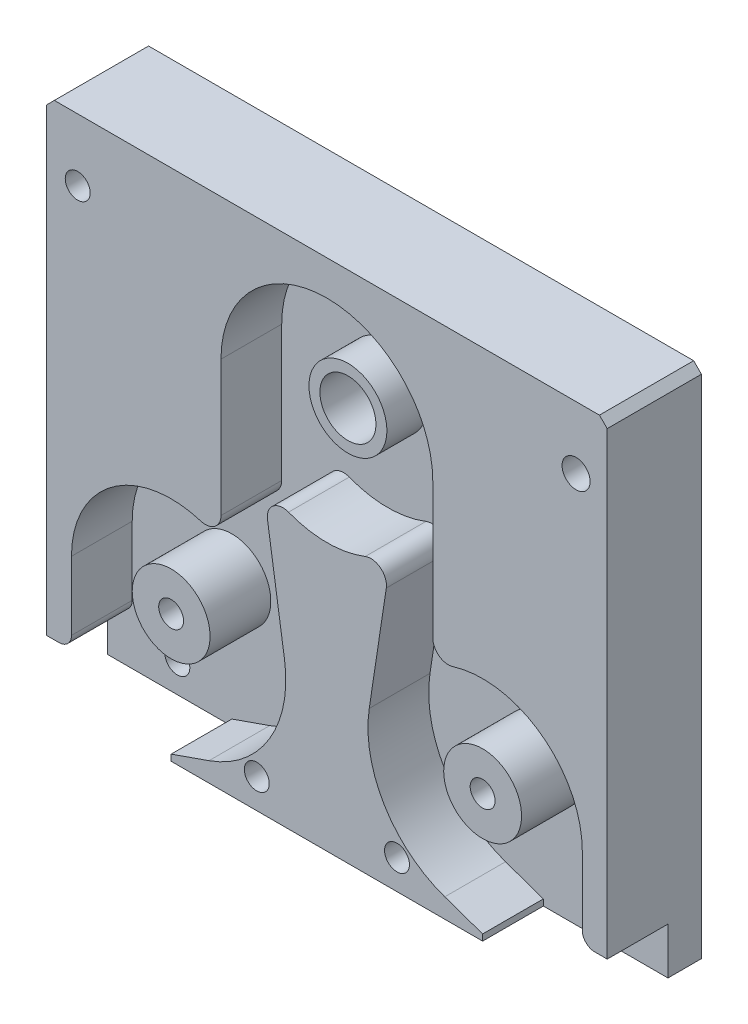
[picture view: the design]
ISO-10303-21;
HEADER;
FILE_DESCRIPTION(('STEP AP214'),'2;1');
FILE_NAME('part.step','',(''),(''),'','','');
FILE_SCHEMA(('AUTOMOTIVE_DESIGN { 1 0 10303 214 1 1 1 1 }'));
ENDSEC;
DATA;
#1=APPLICATION_CONTEXT('core data for automotive mechanical design processes');
#2=APPLICATION_PROTOCOL_DEFINITION('international standard','automotive_design',2000,#1);
#3=PRODUCT_CONTEXT('',#1,'mechanical');
#4=PRODUCT('Part','Part','',(#3));
#5=PRODUCT_RELATED_PRODUCT_CATEGORY('part','',(#4));
#6=PRODUCT_DEFINITION_FORMATION('','',#4);
#7=PRODUCT_DEFINITION_CONTEXT('part definition',#1,'design');
#8=PRODUCT_DEFINITION('design','',#6,#7);
#9=PRODUCT_DEFINITION_SHAPE('','',#8);
#10=(LENGTH_UNIT() NAMED_UNIT(*) SI_UNIT(.MILLI.,.METRE.));
#11=(NAMED_UNIT(*) PLANE_ANGLE_UNIT() SI_UNIT($,.RADIAN.));
#12=(NAMED_UNIT(*) SI_UNIT($,.STERADIAN.) SOLID_ANGLE_UNIT());
#13=UNCERTAINTY_MEASURE_WITH_UNIT(LENGTH_MEASURE(1.E-05),#10,'distance_accuracy_value','');
#14=(GEOMETRIC_REPRESENTATION_CONTEXT(3) GLOBAL_UNCERTAINTY_ASSIGNED_CONTEXT((#13)) GLOBAL_UNIT_ASSIGNED_CONTEXT((#10,
#11,#12)) REPRESENTATION_CONTEXT('',''));
#15=CARTESIAN_POINT('',(0.,0.,0.));
#16=DIRECTION('',(0.,0.,1.));
#17=DIRECTION('',(1.,0.,0.));
#18=AXIS2_PLACEMENT_3D('',#15,#16,#17);
#19=CARTESIAN_POINT('',(-50.,42.5,-20.));
#20=DIRECTION('',(0.,0.,-1.));
#21=DIRECTION('',(-1.,0.,0.));
#22=AXIS2_PLACEMENT_3D('',#19,#20,#21);
#23=PLANE('',#22);
#24=CARTESIAN_POINT('',(-50.,42.5,-20.));
#25=DIRECTION('',(0.,0.,-1.));
#26=DIRECTION('',(-1.,0.,0.));
#27=AXIS2_PLACEMENT_3D('',#24,#25,#26);
#28=CIRCLE('',#27,4.);
#29=CARTESIAN_POINT('',(-54.,42.5,-20.));
#30=VERTEX_POINT('',#29);
#31=EDGE_CURVE('E20',#30,#30,#28,.F.);
#32=ORIENTED_EDGE('',*,*,#31,.T.);
#33=EDGE_LOOP('',(#32));
#34=FACE_BOUND('',#33,.T.);
#35=ADVANCED_FACE('F16',(#34),#23,.F.);
#36=CARTESIAN_POINT('',(-50.,42.5,0.));
#37=DIRECTION('',(0.,0.,-1.));
#38=DIRECTION('',(-1.,0.,0.));
#39=AXIS2_PLACEMENT_3D('',#36,#37,#38);
#40=CYLINDRICAL_SURFACE('',#39,4.);
#41=CARTESIAN_POINT('',(-50.,42.5,0.));
#42=DIRECTION('',(0.,0.,-1.));
#43=DIRECTION('',(-1.,0.,0.));
#44=AXIS2_PLACEMENT_3D('',#41,#42,#43);
#45=CIRCLE('',#44,4.);
#46=CARTESIAN_POINT('',(-54.,42.5,0.));
#47=VERTEX_POINT('',#46);
#48=EDGE_CURVE('E498',#47,#47,#45,.T.);
#49=ORIENTED_EDGE('',*,*,#48,.F.);
#50=EDGE_LOOP('',(#49));
#51=FACE_BOUND('',#50,.T.);
#52=ORIENTED_EDGE('',*,*,#31,.F.);
#53=EDGE_LOOP('',(#52));
#54=FACE_BOUND('',#53,.T.);
#55=ADVANCED_FACE('F506',(#51,#54),#40,.F.);
#56=CARTESIAN_POINT('',(-80.,146.5,-20.));
#57=DIRECTION('',(0.,0.,-1.));
#58=DIRECTION('',(-1.,0.,0.));
#59=AXIS2_PLACEMENT_3D('',#56,#57,#58);
#60=PLANE('',#59);
#61=CARTESIAN_POINT('',(-80.,146.5,-20.));
#62=DIRECTION('',(0.,0.,-1.));
#63=DIRECTION('',(-1.,0.,0.));
#64=AXIS2_PLACEMENT_3D('',#61,#62,#63);
#65=CIRCLE('',#64,4.);
#66=CARTESIAN_POINT('',(-84.,146.5,-20.));
#67=VERTEX_POINT('',#66);
#68=EDGE_CURVE('E496',#67,#67,#65,.F.);
#69=ORIENTED_EDGE('',*,*,#68,.T.);
#70=EDGE_LOOP('',(#69));
#71=FACE_BOUND('',#70,.T.);
#72=ADVANCED_FACE('F508',(#71),#60,.F.);
#73=CARTESIAN_POINT('',(0.,84.,0.));
#74=DIRECTION('',(0.,0.,1.));
#75=DIRECTION('',(1.,0.,0.));
#76=AXIS2_PLACEMENT_3D('',#73,#74,#75);
#77=PLANE('',#76);
#78=CARTESIAN_POINT('',(50.,42.5,0.));
#79=DIRECTION('',(0.,0.,-1.));
#80=DIRECTION('',(-1.,0.,0.));
#81=AXIS2_PLACEMENT_3D('',#78,#79,#80);
#82=CIRCLE('',#81,4.);
#83=CARTESIAN_POINT('',(45.9999999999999,42.5,0.));
#84=VERTEX_POINT('',#83);
#85=EDGE_CURVE('E335',#84,#84,#82,.T.);
#86=ORIENTED_EDGE('',*,*,#85,.T.);
#87=EDGE_LOOP('',(#86));
#88=FACE_BOUND('',#87,.T.);
#89=CARTESIAN_POINT('',(50.,42.5,0.));
#90=DIRECTION('',(0.,0.,-1.));
#91=DIRECTION('',(-1.,0.,0.));
#92=AXIS2_PLACEMENT_3D('',#89,#90,#91);
#93=CIRCLE('',#92,12.5);
#94=CARTESIAN_POINT('',(37.5,42.5,0.));
#95=VERTEX_POINT('',#94);
#96=EDGE_CURVE('E239',#95,#95,#93,.T.);
#97=ORIENTED_EDGE('',*,*,#96,.F.);
#98=EDGE_LOOP('',(#97));
#99=FACE_BOUND('',#98,.T.);
#100=ADVANCED_FACE('F516',(#88,#99),#77,.T.);
#101=CARTESIAN_POINT('',(0.,84.,0.));
#102=DIRECTION('',(0.,0.,1.));
#103=DIRECTION('',(1.,0.,0.));
#104=AXIS2_PLACEMENT_3D('',#101,#102,#103);
#105=PLANE('',#104);
#106=ORIENTED_EDGE('',*,*,#48,.T.);
#107=EDGE_LOOP('',(#106));
#108=FACE_BOUND('',#107,.T.);
#109=CARTESIAN_POINT('',(-50.,42.5,0.));
#110=DIRECTION('',(0.,0.,-1.));
#111=DIRECTION('',(-1.,0.,0.));
#112=AXIS2_PLACEMENT_3D('',#109,#110,#111);
#113=CIRCLE('',#112,12.5);
#114=CARTESIAN_POINT('',(-62.5,42.5,0.));
#115=VERTEX_POINT('',#114);
#116=EDGE_CURVE('E268',#115,#115,#113,.T.);
#117=ORIENTED_EDGE('',*,*,#116,.F.);
#118=EDGE_LOOP('',(#117));
#119=FACE_BOUND('',#118,.T.);
#120=ADVANCED_FACE('F704',(#108,#119),#105,.T.);
#121=CARTESIAN_POINT('',(-80.,146.5,0.));
#122=DIRECTION('',(0.,0.,-1.));
#123=DIRECTION('',(-1.,0.,0.));
#124=AXIS2_PLACEMENT_3D('',#121,#122,#123);
#125=CYLINDRICAL_SURFACE('',#124,4.);
#126=CARTESIAN_POINT('',(-80.,146.5,0.));
#127=DIRECTION('',(0.,0.,-1.));
#128=DIRECTION('',(-1.,0.,0.));
#129=AXIS2_PLACEMENT_3D('',#126,#127,#128);
#130=CIRCLE('',#129,4.);
#131=CARTESIAN_POINT('',(-84.,146.5,0.));
#132=VERTEX_POINT('',#131);
#133=EDGE_CURVE('E471',#132,#132,#130,.T.);
#134=ORIENTED_EDGE('',*,*,#133,.F.);
#135=EDGE_LOOP('',(#134));
#136=FACE_BOUND('',#135,.T.);
#137=ORIENTED_EDGE('',*,*,#68,.F.);
#138=EDGE_LOOP('',(#137));
#139=FACE_BOUND('',#138,.T.);
#140=ADVANCED_FACE('F700',(#136,#139),#125,.F.);
#141=CARTESIAN_POINT('',(50.,42.5,0.));
#142=DIRECTION('',(0.,0.,-1.));
#143=DIRECTION('',(-1.,0.,0.));
#144=AXIS2_PLACEMENT_3D('',#141,#142,#143);
#145=CYLINDRICAL_SURFACE('',#144,4.);
#146=ORIENTED_EDGE('',*,*,#85,.F.);
#147=EDGE_LOOP('',(#146));
#148=FACE_BOUND('',#147,.T.);
#149=CARTESIAN_POINT('',(50.,42.5,-21.25));
#150=DIRECTION('',(0.,0.,-1.));
#151=DIRECTION('',(-1.,0.,0.));
#152=AXIS2_PLACEMENT_3D('',#149,#150,#151);
#153=CIRCLE('',#152,4.);
#154=CARTESIAN_POINT('',(45.9999999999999,42.5,-21.25));
#155=VERTEX_POINT('',#154);
#156=EDGE_CURVE('E462',#155,#155,#153,.T.);
#157=ORIENTED_EDGE('',*,*,#156,.T.);
#158=EDGE_LOOP('',(#157));
#159=FACE_BOUND('',#158,.T.);
#160=ADVANCED_FACE('F696',(#148,#159),#145,.F.);
#161=CARTESIAN_POINT('',(79.9999999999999,146.5,0.));
#162=DIRECTION('',(0.,0.,-1.));
#163=DIRECTION('',(-1.,0.,0.));
#164=AXIS2_PLACEMENT_3D('',#161,#162,#163);
#165=CYLINDRICAL_SURFACE('',#164,4.5);
#166=CARTESIAN_POINT('',(79.9999999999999,146.5,0.));
#167=DIRECTION('',(0.,0.,-1.));
#168=DIRECTION('',(-1.,0.,0.));
#169=AXIS2_PLACEMENT_3D('',#166,#167,#168);
#170=CIRCLE('',#169,4.5);
#171=CARTESIAN_POINT('',(75.4999999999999,146.5,0.));
#172=VERTEX_POINT('',#171);
#173=EDGE_CURVE('E468',#172,#172,#170,.T.);
#174=ORIENTED_EDGE('',*,*,#173,.F.);
#175=EDGE_LOOP('',(#174));
#176=FACE_BOUND('',#175,.T.);
#177=CARTESIAN_POINT('',(79.9999999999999,146.5,-21.25));
#178=DIRECTION('',(0.,0.,-1.));
#179=DIRECTION('',(-1.,0.,0.));
#180=AXIS2_PLACEMENT_3D('',#177,#178,#179);
#181=CIRCLE('',#180,4.5);
#182=CARTESIAN_POINT('',(75.4999999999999,146.5,-21.25));
#183=VERTEX_POINT('',#182);
#184=EDGE_CURVE('E354',#183,#183,#181,.T.);
#185=ORIENTED_EDGE('',*,*,#184,.T.);
#186=EDGE_LOOP('',(#185));
#187=FACE_BOUND('',#186,.T.);
#188=ADVANCED_FACE('F692',(#176,#187),#165,.F.);
#189=CARTESIAN_POINT('',(-50.,3.5,0.));
#190=DIRECTION('',(0.330013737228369,-0.943976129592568,0.));
#191=DIRECTION('',(0.943976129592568,0.330013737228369,0.));
#192=AXIS2_PLACEMENT_3D('',#189,#190,#191);
#193=PLANE('',#192);
#194=DIRECTION('',(0.,0.,-1.));
#195=VECTOR('',#194,1.);
#196=CARTESIAN_POINT('',(-50.,3.5,0.));
#197=LINE('',#196,#195);
#198=CARTESIAN_POINT('',(-50.,3.5,-19.5));
#199=VERTEX_POINT('',#198);
#200=CARTESIAN_POINT('',(-50.,3.5,0.));
#201=VERTEX_POINT('',#200);
#202=EDGE_CURVE('E301',#199,#201,#197,.F.);
#203=ORIENTED_EDGE('',*,*,#202,.T.);
#204=DIRECTION('',(-0.943976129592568,-0.330013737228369,0.));
#205=VECTOR('',#204,1.);
#206=CARTESIAN_POINT('',(-37.8505214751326,7.74745360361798,0.));
#207=LINE('',#206,#205);
#208=CARTESIAN_POINT('',(-37.8505214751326,7.74745360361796,0.));
#209=VERTEX_POINT('',#208);
#210=EDGE_CURVE('E349',#209,#201,#207,.T.);
#211=ORIENTED_EDGE('',*,*,#210,.F.);
#212=DIRECTION('',(0.,0.,-1.));
#213=VECTOR('',#212,1.);
#214=CARTESIAN_POINT('',(-37.8505214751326,7.74745360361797,0.));
#215=LINE('',#214,#213);
#216=CARTESIAN_POINT('',(-37.8505214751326,7.74745360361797,-19.5));
#217=VERTEX_POINT('',#216);
#218=EDGE_CURVE('E332',#209,#217,#215,.T.);
#219=ORIENTED_EDGE('',*,*,#218,.T.);
#220=DIRECTION('',(0.943976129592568,0.33001373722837,0.));
#221=VECTOR('',#220,1.);
#222=CARTESIAN_POINT('',(-50.,3.5,-19.5));
#223=LINE('',#222,#221);
#224=EDGE_CURVE('E339',#199,#217,#223,.T.);
#225=ORIENTED_EDGE('',*,*,#224,.F.);
#226=EDGE_LOOP('',(#203,#211,#219,#225));
#227=FACE_BOUND('',#226,.T.);
#228=ADVANCED_FACE('F688',(#227),#193,.F.);
#229=CARTESIAN_POINT('',(-50.,42.5,0.));
#230=DIRECTION('',(0.,0.,-1.));
#231=DIRECTION('',(-1.,0.,0.));
#232=AXIS2_PLACEMENT_3D('',#229,#230,#231);
#233=CYLINDRICAL_SURFACE('',#232,36.8150690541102);
#234=ORIENTED_EDGE('',*,*,#218,.F.);
#235=CARTESIAN_POINT('',(-50.,42.5,0.));
#236=DIRECTION('',(0.,0.,-1.));
#237=DIRECTION('',(-1.,0.,0.));
#238=AXIS2_PLACEMENT_3D('',#235,#236,#237);
#239=CIRCLE('',#238,36.8150690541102);
#240=CARTESIAN_POINT('',(-13.5982629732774,48.0011681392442,0.));
#241=VERTEX_POINT('',#240);
#242=EDGE_CURVE('E443',#241,#209,#239,.T.);
#243=ORIENTED_EDGE('',*,*,#242,.F.);
#244=DIRECTION('',(0.,0.,1.));
#245=VECTOR('',#244,1.);
#246=CARTESIAN_POINT('',(-13.5982629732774,48.0011681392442,0.));
#247=LINE('',#246,#245);
#248=CARTESIAN_POINT('',(-13.5982629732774,48.0011681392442,-19.5));
#249=VERTEX_POINT('',#248);
#250=EDGE_CURVE('E329',#241,#249,#247,.F.);
#251=ORIENTED_EDGE('',*,*,#250,.T.);
#252=CARTESIAN_POINT('',(-50.,42.5,-19.5));
#253=DIRECTION('',(0.,0.,-1.));
#254=DIRECTION('',(-1.,0.,0.));
#255=AXIS2_PLACEMENT_3D('',#252,#253,#254);
#256=CIRCLE('',#255,36.8150690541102);
#257=EDGE_CURVE('E441',#217,#249,#256,.F.);
#258=ORIENTED_EDGE('',*,*,#257,.F.);
#259=EDGE_LOOP('',(#234,#243,#251,#258));
#260=FACE_BOUND('',#259,.T.);
#261=ADVANCED_FACE('F684',(#260),#233,.F.);
#262=CARTESIAN_POINT('',(-13.5982629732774,48.0011681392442,0.));
#263=DIRECTION('',(0.988772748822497,0.149427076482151,0.));
#264=DIRECTION('',(-0.149427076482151,0.988772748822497,0.));
#265=AXIS2_PLACEMENT_3D('',#262,#263,#264);
#266=PLANE('',#265);
#267=ORIENTED_EDGE('',*,*,#250,.F.);
#268=DIRECTION('',(0.149427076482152,-0.988772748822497,0.));
#269=VECTOR('',#268,1.);
#270=CARTESIAN_POINT('',(-19.0688637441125,84.2006380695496,0.));
#271=LINE('',#270,#269);
#272=CARTESIAN_POINT('',(-19.0688637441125,84.2006380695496,0.));
#273=VERTEX_POINT('',#272);
#274=EDGE_CURVE('E446',#273,#241,#271,.T.);
#275=ORIENTED_EDGE('',*,*,#274,.F.);
#276=DIRECTION('',(0.,0.,-1.));
#277=VECTOR('',#276,1.);
#278=CARTESIAN_POINT('',(-19.0688637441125,84.2006380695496,0.));
#279=LINE('',#278,#277);
#280=CARTESIAN_POINT('',(-19.0688637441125,84.2006380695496,-19.5));
#281=VERTEX_POINT('',#280);
#282=EDGE_CURVE('E327',#281,#273,#279,.F.);
#283=ORIENTED_EDGE('',*,*,#282,.F.);
#284=DIRECTION('',(-0.149427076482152,0.988772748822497,0.));
#285=VECTOR('',#284,1.);
#286=CARTESIAN_POINT('',(-13.5982629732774,48.0011681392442,-19.5));
#287=LINE('',#286,#285);
#288=EDGE_CURVE('E440',#249,#281,#287,.T.);
#289=ORIENTED_EDGE('',*,*,#288,.F.);
#290=EDGE_LOOP('',(#267,#275,#283,#289));
#291=FACE_BOUND('',#290,.T.);
#292=ADVANCED_FACE('F680',(#291),#266,.F.);
#293=CARTESIAN_POINT('',(-14.125,84.9477734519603,0.));
#294=DIRECTION('',(0.,0.,-1.));
#295=DIRECTION('',(-1.,0.,0.));
#296=AXIS2_PLACEMENT_3D('',#293,#294,#295);
#297=CYLINDRICAL_SURFACE('',#296,5.);
#298=CARTESIAN_POINT('',(-14.125,84.9477734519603,0.));
#299=DIRECTION('',(0.,0.,-1.));
#300=DIRECTION('',(-1.,0.,0.));
#301=AXIS2_PLACEMENT_3D('',#298,#299,#300);
#302=CIRCLE('',#301,5.);
#303=CARTESIAN_POINT('',(-12.3141025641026,89.6083153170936,0.));
#304=VERTEX_POINT('',#303);
#305=EDGE_CURVE('E447',#304,#273,#302,.F.);
#306=ORIENTED_EDGE('',*,*,#305,.F.);
#307=DIRECTION('',(0.,0.,-1.));
#308=VECTOR('',#307,1.);
#309=CARTESIAN_POINT('',(-12.3141025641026,89.6083153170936,0.));
#310=LINE('',#309,#308);
#311=CARTESIAN_POINT('',(-12.3141025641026,89.6083153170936,-19.5));
#312=VERTEX_POINT('',#311);
#313=EDGE_CURVE('E324',#304,#312,#310,.T.);
#314=ORIENTED_EDGE('',*,*,#313,.T.);
#315=CARTESIAN_POINT('',(-14.125,84.9477734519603,-19.5));
#316=DIRECTION('',(0.,0.,-1.));
#317=DIRECTION('',(-1.,0.,0.));
#318=AXIS2_PLACEMENT_3D('',#315,#316,#317);
#319=CIRCLE('',#318,5.);
#320=EDGE_CURVE('E438',#281,#312,#319,.T.);
#321=ORIENTED_EDGE('',*,*,#320,.F.);
#322=ORIENTED_EDGE('',*,*,#282,.T.);
#323=EDGE_LOOP('',(#306,#314,#321,#322));
#324=FACE_BOUND('',#323,.T.);
#325=ADVANCED_FACE('F676',(#324),#297,.T.);
#326=CARTESIAN_POINT('',(0.,121.3,0.));
#327=DIRECTION('',(0.,0.,-1.));
#328=DIRECTION('',(-1.,0.,0.));
#329=AXIS2_PLACEMENT_3D('',#326,#327,#328);
#330=CYLINDRICAL_SURFACE('',#329,34.);
#331=ORIENTED_EDGE('',*,*,#313,.F.);
#332=CARTESIAN_POINT('',(0.,121.3,0.));
#333=DIRECTION('',(0.,0.,-1.));
#334=DIRECTION('',(-1.,0.,0.));
#335=AXIS2_PLACEMENT_3D('',#332,#333,#334);
#336=CIRCLE('',#335,34.);
#337=CARTESIAN_POINT('',(12.3141025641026,89.6083153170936,0.));
#338=VERTEX_POINT('',#337);
#339=EDGE_CURVE('E450',#338,#304,#336,.T.);
#340=ORIENTED_EDGE('',*,*,#339,.F.);
#341=DIRECTION('',(0.,0.,-1.));
#342=VECTOR('',#341,1.);
#343=CARTESIAN_POINT('',(12.3141025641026,89.6083153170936,0.));
#344=LINE('',#343,#342);
#345=CARTESIAN_POINT('',(12.3141025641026,89.6083153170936,-19.5));
#346=VERTEX_POINT('',#345);
#347=EDGE_CURVE('E322',#346,#338,#344,.F.);
#348=ORIENTED_EDGE('',*,*,#347,.F.);
#349=CARTESIAN_POINT('',(0.,121.3,-19.5));
#350=DIRECTION('',(0.,0.,-1.));
#351=DIRECTION('',(-1.,0.,0.));
#352=AXIS2_PLACEMENT_3D('',#349,#350,#351);
#353=CIRCLE('',#352,34.);
#354=EDGE_CURVE('E436',#312,#346,#353,.F.);
#355=ORIENTED_EDGE('',*,*,#354,.F.);
#356=EDGE_LOOP('',(#331,#340,#348,#355));
#357=FACE_BOUND('',#356,.T.);
#358=ADVANCED_FACE('F672',(#357),#330,.F.);
#359=CARTESIAN_POINT('',(14.125,84.9477734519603,0.));
#360=DIRECTION('',(0.,0.,-1.));
#361=DIRECTION('',(-1.,0.,0.));
#362=AXIS2_PLACEMENT_3D('',#359,#360,#361);
#363=CYLINDRICAL_SURFACE('',#362,5.);
#364=CARTESIAN_POINT('',(14.125,84.9477734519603,0.));
#365=DIRECTION('',(0.,0.,-1.));
#366=DIRECTION('',(-1.,0.,0.));
#367=AXIS2_PLACEMENT_3D('',#364,#365,#366);
#368=CIRCLE('',#367,5.);
#369=CARTESIAN_POINT('',(19.0688637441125,84.2006380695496,0.));
#370=VERTEX_POINT('',#369);
#371=EDGE_CURVE('E453',#370,#338,#368,.F.);
#372=ORIENTED_EDGE('',*,*,#371,.F.);
#373=DIRECTION('',(0.,0.,1.));
#374=VECTOR('',#373,1.);
#375=CARTESIAN_POINT('',(19.0688637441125,84.2006380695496,0.));
#376=LINE('',#375,#374);
#377=CARTESIAN_POINT('',(19.0688637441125,84.2006380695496,-19.5));
#378=VERTEX_POINT('',#377);
#379=EDGE_CURVE('E319',#370,#378,#376,.F.);
#380=ORIENTED_EDGE('',*,*,#379,.T.);
#381=CARTESIAN_POINT('',(14.125,84.9477734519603,-19.5));
#382=DIRECTION('',(0.,0.,-1.));
#383=DIRECTION('',(-1.,0.,0.));
#384=AXIS2_PLACEMENT_3D('',#381,#382,#383);
#385=CIRCLE('',#384,5.);
#386=EDGE_CURVE('E434',#346,#378,#385,.T.);
#387=ORIENTED_EDGE('',*,*,#386,.F.);
#388=ORIENTED_EDGE('',*,*,#347,.T.);
#389=EDGE_LOOP('',(#372,#380,#387,#388));
#390=FACE_BOUND('',#389,.T.);
#391=ADVANCED_FACE('F668',(#390),#363,.T.);
#392=CARTESIAN_POINT('',(19.0688637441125,84.2006380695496,0.));
#393=DIRECTION('',(-0.988772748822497,0.14942707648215,0.));
#394=DIRECTION('',(-0.14942707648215,-0.988772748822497,0.));
#395=AXIS2_PLACEMENT_3D('',#392,#393,#394);
#396=PLANE('',#395);
#397=ORIENTED_EDGE('',*,*,#379,.F.);
#398=DIRECTION('',(0.14942707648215,0.988772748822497,0.));
#399=VECTOR('',#398,1.);
#400=CARTESIAN_POINT('',(13.5982629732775,48.0011681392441,0.));
#401=LINE('',#400,#399);
#402=CARTESIAN_POINT('',(13.5982629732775,48.0011681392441,0.));
#403=VERTEX_POINT('',#402);
#404=EDGE_CURVE('E456',#403,#370,#401,.T.);
#405=ORIENTED_EDGE('',*,*,#404,.F.);
#406=DIRECTION('',(0.,0.,-1.));
#407=VECTOR('',#406,1.);
#408=CARTESIAN_POINT('',(13.5982629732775,48.0011681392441,0.));
#409=LINE('',#408,#407);
#410=CARTESIAN_POINT('',(13.5982629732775,48.0011681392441,-19.5));
#411=VERTEX_POINT('',#410);
#412=EDGE_CURVE('E310',#403,#411,#409,.T.);
#413=ORIENTED_EDGE('',*,*,#412,.T.);
#414=DIRECTION('',(-0.14942707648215,-0.988772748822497,0.));
#415=VECTOR('',#414,1.);
#416=CARTESIAN_POINT('',(19.0688637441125,84.2006380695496,-19.5));
#417=LINE('',#416,#415);
#418=EDGE_CURVE('E433',#378,#411,#417,.T.);
#419=ORIENTED_EDGE('',*,*,#418,.F.);
#420=EDGE_LOOP('',(#397,#405,#413,#419));
#421=FACE_BOUND('',#420,.T.);
#422=ADVANCED_FACE('F664',(#421),#396,.F.);
#423=CARTESIAN_POINT('',(50.,42.5,0.));
#424=DIRECTION('',(0.,0.,-1.));
#425=DIRECTION('',(-1.,0.,0.));
#426=AXIS2_PLACEMENT_3D('',#423,#424,#425);
#427=CYLINDRICAL_SURFACE('',#426,36.8150690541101);
#428=ORIENTED_EDGE('',*,*,#412,.F.);
#429=CARTESIAN_POINT('',(50.,42.5,0.));
#430=DIRECTION('',(0.,0.,-1.));
#431=DIRECTION('',(-1.,0.,0.));
#432=AXIS2_PLACEMENT_3D('',#429,#430,#431);
#433=CIRCLE('',#432,36.8150690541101);
#434=CARTESIAN_POINT('',(37.8505214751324,7.74745360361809,0.));
#435=VERTEX_POINT('',#434);
#436=EDGE_CURVE('E457',#435,#403,#433,.T.);
#437=ORIENTED_EDGE('',*,*,#436,.F.);
#438=DIRECTION('',(0.,0.,1.));
#439=VECTOR('',#438,1.);
#440=CARTESIAN_POINT('',(37.8505214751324,7.7474536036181,0.));
#441=LINE('',#440,#439);
#442=CARTESIAN_POINT('',(37.8505214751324,7.7474536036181,-19.5));
#443=VERTEX_POINT('',#442);
#444=EDGE_CURVE('E299',#435,#443,#441,.F.);
#445=ORIENTED_EDGE('',*,*,#444,.T.);
#446=CARTESIAN_POINT('',(50.,42.5,-19.5));
#447=DIRECTION('',(0.,0.,-1.));
#448=DIRECTION('',(-1.,0.,0.));
#449=AXIS2_PLACEMENT_3D('',#446,#447,#448);
#450=CIRCLE('',#449,36.8150690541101);
#451=EDGE_CURVE('E431',#411,#443,#450,.F.);
#452=ORIENTED_EDGE('',*,*,#451,.F.);
#453=EDGE_LOOP('',(#428,#437,#445,#452));
#454=FACE_BOUND('',#453,.T.);
#455=ADVANCED_FACE('F660',(#454),#427,.F.);
#456=CARTESIAN_POINT('',(37.8505214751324,7.7474536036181,0.));
#457=DIRECTION('',(-0.330013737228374,-0.943976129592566,0.));
#458=DIRECTION('',(0.943976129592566,-0.330013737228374,0.));
#459=AXIS2_PLACEMENT_3D('',#456,#457,#458);
#460=PLANE('',#459);
#461=ORIENTED_EDGE('',*,*,#444,.F.);
#462=DIRECTION('',(-0.943976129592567,0.330013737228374,0.));
#463=VECTOR('',#462,1.);
#464=CARTESIAN_POINT('',(50.,3.5,0.));
#465=LINE('',#464,#463);
#466=CARTESIAN_POINT('',(50.,3.50000000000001,0.));
#467=VERTEX_POINT('',#466);
#468=EDGE_CURVE('E353',#467,#435,#465,.T.);
#469=ORIENTED_EDGE('',*,*,#468,.F.);
#470=DIRECTION('',(0.,0.,1.));
#471=VECTOR('',#470,1.);
#472=CARTESIAN_POINT('',(50.,3.5,0.));
#473=LINE('',#472,#471);
#474=CARTESIAN_POINT('',(50.,3.5,-19.5));
#475=VERTEX_POINT('',#474);
#476=EDGE_CURVE('E267',#467,#475,#473,.F.);
#477=ORIENTED_EDGE('',*,*,#476,.T.);
#478=DIRECTION('',(0.943976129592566,-0.330013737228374,0.));
#479=VECTOR('',#478,1.);
#480=CARTESIAN_POINT('',(37.8505214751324,7.7474536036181,-19.5));
#481=LINE('',#480,#479);
#482=EDGE_CURVE('E316',#443,#475,#481,.T.);
#483=ORIENTED_EDGE('',*,*,#482,.F.);
#484=EDGE_LOOP('',(#461,#469,#477,#483));
#485=FACE_BOUND('',#484,.T.);
#486=ADVANCED_FACE('F656',(#485),#460,.F.);
#487=CARTESIAN_POINT('',(86.,20.5,0.));
#488=DIRECTION('',(0.,0.,-1.));
#489=DIRECTION('',(-1.,0.,0.));
#490=AXIS2_PLACEMENT_3D('',#487,#488,#489);
#491=CYLINDRICAL_SURFACE('',#490,4.00000000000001);
#492=CARTESIAN_POINT('',(86.,20.5,0.));
#493=DIRECTION('',(0.,0.,-1.));
#494=DIRECTION('',(-1.,0.,0.));
#495=AXIS2_PLACEMENT_3D('',#492,#493,#494);
#496=CIRCLE('',#495,4.00000000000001);
#497=CARTESIAN_POINT('',(82.,20.5,0.));
#498=VERTEX_POINT('',#497);
#499=CARTESIAN_POINT('',(86.,16.5,0.));
#500=VERTEX_POINT('',#499);
#501=EDGE_CURVE('E474',#498,#500,#496,.F.);
#502=ORIENTED_EDGE('',*,*,#501,.F.);
#503=DIRECTION('',(0.,0.,-1.));
#504=VECTOR('',#503,1.);
#505=CARTESIAN_POINT('',(82.,20.5,0.));
#506=LINE('',#505,#504);
#507=CARTESIAN_POINT('',(82.,20.5,-19.5));
#508=VERTEX_POINT('',#507);
#509=EDGE_CURVE('E296',#498,#508,#506,.T.);
#510=ORIENTED_EDGE('',*,*,#509,.T.);
#511=CARTESIAN_POINT('',(86.,20.5,-19.5));
#512=DIRECTION('',(0.,0.,-1.));
#513=DIRECTION('',(-1.,0.,0.));
#514=AXIS2_PLACEMENT_3D('',#511,#512,#513);
#515=CIRCLE('',#514,4.00000000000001);
#516=CARTESIAN_POINT('',(86.,16.5,-19.5));
#517=VERTEX_POINT('',#516);
#518=EDGE_CURVE('E429',#517,#508,#515,.T.);
#519=ORIENTED_EDGE('',*,*,#518,.F.);
#520=DIRECTION('',(0.,0.,1.));
#521=VECTOR('',#520,1.);
#522=CARTESIAN_POINT('',(86.,16.5,0.));
#523=LINE('',#522,#521);
#524=EDGE_CURVE('E265',#517,#500,#523,.T.);
#525=ORIENTED_EDGE('',*,*,#524,.T.);
#526=EDGE_LOOP('',(#502,#510,#519,#525));
#527=FACE_BOUND('',#526,.T.);
#528=ADVANCED_FACE('F652',(#527),#491,.T.);
#529=CARTESIAN_POINT('',(82.,20.5,0.));
#530=DIRECTION('',(1.,0.,0.));
#531=DIRECTION('',(0.,0.,-1.));
#532=AXIS2_PLACEMENT_3D('',#529,#530,#531);
#533=PLANE('',#532);
#534=ORIENTED_EDGE('',*,*,#509,.F.);
#535=DIRECTION('',(0.,1.,0.));
#536=VECTOR('',#535,1.);
#537=CARTESIAN_POINT('',(81.9999999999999,84.,0.));
#538=LINE('',#537,#536);
#539=CARTESIAN_POINT('',(81.9999999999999,42.5,0.));
#540=VERTEX_POINT('',#539);
#541=EDGE_CURVE('E477',#540,#498,#538,.F.);
#542=ORIENTED_EDGE('',*,*,#541,.F.);
#543=DIRECTION('',(0.,0.,-1.));
#544=VECTOR('',#543,1.);
#545=CARTESIAN_POINT('',(81.9999999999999,42.5,0.));
#546=LINE('',#545,#544);
#547=CARTESIAN_POINT('',(81.9999999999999,42.5,-19.5));
#548=VERTEX_POINT('',#547);
#549=EDGE_CURVE('E293',#540,#548,#546,.T.);
#550=ORIENTED_EDGE('',*,*,#549,.T.);
#551=DIRECTION('',(0.,1.,0.));
#552=VECTOR('',#551,1.);
#553=CARTESIAN_POINT('',(82.,61.3926362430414,-19.5));
#554=LINE('',#553,#552);
#555=EDGE_CURVE('E428',#508,#548,#554,.T.);
#556=ORIENTED_EDGE('',*,*,#555,.F.);
#557=EDGE_LOOP('',(#534,#542,#550,#556));
#558=FACE_BOUND('',#557,.T.);
#559=ADVANCED_FACE('F648',(#558),#533,.F.);
#560=CARTESIAN_POINT('',(50.,42.5,0.));
#561=DIRECTION('',(0.,0.,-1.));
#562=DIRECTION('',(-1.,0.,0.));
#563=AXIS2_PLACEMENT_3D('',#560,#561,#562);
#564=CYLINDRICAL_SURFACE('',#563,32.);
#565=ORIENTED_EDGE('',*,*,#549,.F.);
#566=CARTESIAN_POINT('',(50.,42.5,0.));
#567=DIRECTION('',(0.,0.,-1.));
#568=DIRECTION('',(-1.,0.,0.));
#569=AXIS2_PLACEMENT_3D('',#566,#567,#568);
#570=CIRCLE('',#569,32.);
#571=CARTESIAN_POINT('',(40.4864864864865,73.0531186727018,0.));
#572=VERTEX_POINT('',#571);
#573=EDGE_CURVE('E478',#572,#540,#570,.T.);
#574=ORIENTED_EDGE('',*,*,#573,.F.);
#575=DIRECTION('',(0.,0.,-1.));
#576=VECTOR('',#575,1.);
#577=CARTESIAN_POINT('',(40.4864864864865,73.0531186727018,0.));
#578=LINE('',#577,#576);
#579=CARTESIAN_POINT('',(40.4864864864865,73.0531186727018,-19.5));
#580=VERTEX_POINT('',#579);
#581=EDGE_CURVE('E291',#580,#572,#578,.F.);
#582=ORIENTED_EDGE('',*,*,#581,.F.);
#583=CARTESIAN_POINT('',(50.,42.5,-19.5));
#584=DIRECTION('',(0.,0.,-1.));
#585=DIRECTION('',(-1.,0.,0.));
#586=AXIS2_PLACEMENT_3D('',#583,#584,#585);
#587=CIRCLE('',#586,32.);
#588=EDGE_CURVE('E426',#548,#580,#587,.F.);
#589=ORIENTED_EDGE('',*,*,#588,.F.);
#590=EDGE_LOOP('',(#565,#574,#582,#589));
#591=FACE_BOUND('',#590,.T.);
#592=ADVANCED_FACE('F644',(#591),#564,.F.);
#593=CARTESIAN_POINT('',(39.,77.8270434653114,0.));
#594=DIRECTION('',(0.,0.,-1.));
#595=DIRECTION('',(-1.,0.,0.));
#596=AXIS2_PLACEMENT_3D('',#593,#594,#595);
#597=CYLINDRICAL_SURFACE('',#596,5.);
#598=CARTESIAN_POINT('',(39.,77.8270434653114,0.));
#599=DIRECTION('',(0.,0.,-1.));
#600=DIRECTION('',(-1.,0.,0.));
#601=AXIS2_PLACEMENT_3D('',#598,#599,#600);
#602=CIRCLE('',#601,5.);
#603=CARTESIAN_POINT('',(34.,77.8270434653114,0.));
#604=VERTEX_POINT('',#603);
#605=EDGE_CURVE('E481',#604,#572,#602,.F.);
#606=ORIENTED_EDGE('',*,*,#605,.F.);
#607=DIRECTION('',(0.,0.,-1.));
#608=VECTOR('',#607,1.);
#609=CARTESIAN_POINT('',(34.,77.8270434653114,0.));
#610=LINE('',#609,#608);
#611=CARTESIAN_POINT('',(34.,77.8270434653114,-19.5));
#612=VERTEX_POINT('',#611);
#613=EDGE_CURVE('E288',#604,#612,#610,.T.);
#614=ORIENTED_EDGE('',*,*,#613,.T.);
#615=CARTESIAN_POINT('',(39.,77.8270434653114,-19.5));
#616=DIRECTION('',(0.,0.,-1.));
#617=DIRECTION('',(-1.,0.,0.));
#618=AXIS2_PLACEMENT_3D('',#615,#616,#617);
#619=CIRCLE('',#618,5.);
#620=EDGE_CURVE('E424',#580,#612,#619,.T.);
#621=ORIENTED_EDGE('',*,*,#620,.F.);
#622=ORIENTED_EDGE('',*,*,#581,.T.);
#623=EDGE_LOOP('',(#606,#614,#621,#622));
#624=FACE_BOUND('',#623,.T.);
#625=ADVANCED_FACE('F640',(#624),#597,.T.);
#626=CARTESIAN_POINT('',(34.,77.8270434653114,0.));
#627=DIRECTION('',(1.,0.,0.));
#628=DIRECTION('',(0.,0.,-1.));
#629=AXIS2_PLACEMENT_3D('',#626,#627,#628);
#630=PLANE('',#629);
#631=ORIENTED_EDGE('',*,*,#613,.F.);
#632=DIRECTION('',(0.,1.,0.));
#633=VECTOR('',#632,1.);
#634=CARTESIAN_POINT('',(34.,84.,0.));
#635=LINE('',#634,#633);
#636=CARTESIAN_POINT('',(34.,121.3,0.));
#637=VERTEX_POINT('',#636);
#638=EDGE_CURVE('E484',#637,#604,#635,.F.);
#639=ORIENTED_EDGE('',*,*,#638,.F.);
#640=DIRECTION('',(0.,0.,-1.));
#641=VECTOR('',#640,1.);
#642=CARTESIAN_POINT('',(34.,121.3,0.));
#643=LINE('',#642,#641);
#644=CARTESIAN_POINT('',(34.,121.3,-19.5));
#645=VERTEX_POINT('',#644);
#646=EDGE_CURVE('E285',#637,#645,#643,.T.);
#647=ORIENTED_EDGE('',*,*,#646,.T.);
#648=DIRECTION('',(0.,1.,0.));
#649=VECTOR('',#648,1.);
#650=CARTESIAN_POINT('',(34.,61.3926362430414,-19.5));
#651=LINE('',#650,#649);
#652=EDGE_CURVE('E423',#612,#645,#651,.T.);
#653=ORIENTED_EDGE('',*,*,#652,.F.);
#654=EDGE_LOOP('',(#631,#639,#647,#653));
#655=FACE_BOUND('',#654,.T.);
#656=ADVANCED_FACE('F636',(#655),#630,.F.);
#657=CARTESIAN_POINT('',(0.,121.3,0.));
#658=DIRECTION('',(0.,0.,-1.));
#659=DIRECTION('',(-1.,0.,0.));
#660=AXIS2_PLACEMENT_3D('',#657,#658,#659);
#661=CYLINDRICAL_SURFACE('',#660,34.);
#662=ORIENTED_EDGE('',*,*,#646,.F.);
#663=CARTESIAN_POINT('',(0.,121.3,0.));
#664=DIRECTION('',(0.,0.,-1.));
#665=DIRECTION('',(-1.,0.,0.));
#666=AXIS2_PLACEMENT_3D('',#663,#664,#665);
#667=CIRCLE('',#666,34.);
#668=CARTESIAN_POINT('',(-34.,121.3,0.));
#669=VERTEX_POINT('',#668);
#670=EDGE_CURVE('E485',#669,#637,#667,.T.);
#671=ORIENTED_EDGE('',*,*,#670,.F.);
#672=DIRECTION('',(0.,0.,1.));
#673=VECTOR('',#672,1.);
#674=CARTESIAN_POINT('',(-34.,121.3,0.));
#675=LINE('',#674,#673);
#676=CARTESIAN_POINT('',(-34.,121.3,-19.5));
#677=VERTEX_POINT('',#676);
#678=EDGE_CURVE('E282',#669,#677,#675,.F.);
#679=ORIENTED_EDGE('',*,*,#678,.T.);
#680=CARTESIAN_POINT('',(0.,121.3,-19.5));
#681=DIRECTION('',(0.,0.,-1.));
#682=DIRECTION('',(-1.,0.,0.));
#683=AXIS2_PLACEMENT_3D('',#680,#681,#682);
#684=CIRCLE('',#683,34.);
#685=EDGE_CURVE('E421',#645,#677,#684,.F.);
#686=ORIENTED_EDGE('',*,*,#685,.F.);
#687=EDGE_LOOP('',(#662,#671,#679,#686));
#688=FACE_BOUND('',#687,.T.);
#689=ADVANCED_FACE('F632',(#688),#661,.F.);
#690=CARTESIAN_POINT('',(-34.,121.3,0.));
#691=DIRECTION('',(-1.,0.,0.));
#692=DIRECTION('',(0.,0.,1.));
#693=AXIS2_PLACEMENT_3D('',#690,#691,#692);
#694=PLANE('',#693);
#695=ORIENTED_EDGE('',*,*,#678,.F.);
#696=DIRECTION('',(0.,1.,0.));
#697=VECTOR('',#696,1.);
#698=CARTESIAN_POINT('',(-34.,84.,0.));
#699=LINE('',#698,#697);
#700=CARTESIAN_POINT('',(-34.,77.8270434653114,0.));
#701=VERTEX_POINT('',#700);
#702=EDGE_CURVE('E260',#701,#669,#699,.T.);
#703=ORIENTED_EDGE('',*,*,#702,.F.);
#704=DIRECTION('',(0.,0.,-1.));
#705=VECTOR('',#704,1.);
#706=CARTESIAN_POINT('',(-34.,77.8270434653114,0.));
#707=LINE('',#706,#705);
#708=CARTESIAN_POINT('',(-34.,77.8270434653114,-19.5));
#709=VERTEX_POINT('',#708);
#710=EDGE_CURVE('E280',#709,#701,#707,.F.);
#711=ORIENTED_EDGE('',*,*,#710,.F.);
#712=DIRECTION('',(0.,1.,0.));
#713=VECTOR('',#712,1.);
#714=CARTESIAN_POINT('',(-34.,61.3926362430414,-19.5));
#715=LINE('',#714,#713);
#716=EDGE_CURVE('E420',#677,#709,#715,.F.);
#717=ORIENTED_EDGE('',*,*,#716,.F.);
#718=EDGE_LOOP('',(#695,#703,#711,#717));
#719=FACE_BOUND('',#718,.T.);
#720=ADVANCED_FACE('F628',(#719),#694,.F.);
#721=CARTESIAN_POINT('',(-39.,77.8270434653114,0.));
#722=DIRECTION('',(0.,0.,-1.));
#723=DIRECTION('',(-1.,0.,0.));
#724=AXIS2_PLACEMENT_3D('',#721,#722,#723);
#725=CYLINDRICAL_SURFACE('',#724,5.);
#726=CARTESIAN_POINT('',(-39.,77.8270434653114,0.));
#727=DIRECTION('',(0.,0.,-1.));
#728=DIRECTION('',(-1.,0.,0.));
#729=AXIS2_PLACEMENT_3D('',#726,#727,#728);
#730=CIRCLE('',#729,5.);
#731=CARTESIAN_POINT('',(-40.4864864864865,73.0531186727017,0.));
#732=VERTEX_POINT('',#731);
#733=EDGE_CURVE('E256',#732,#701,#730,.F.);
#734=ORIENTED_EDGE('',*,*,#733,.F.);
#735=DIRECTION('',(0.,0.,-1.));
#736=VECTOR('',#735,1.);
#737=CARTESIAN_POINT('',(-40.4864864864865,73.0531186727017,0.));
#738=LINE('',#737,#736);
#739=CARTESIAN_POINT('',(-40.4864864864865,73.0531186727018,-19.5));
#740=VERTEX_POINT('',#739);
#741=EDGE_CURVE('E277',#732,#740,#738,.T.);
#742=ORIENTED_EDGE('',*,*,#741,.T.);
#743=CARTESIAN_POINT('',(-39.,77.8270434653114,-19.5));
#744=DIRECTION('',(0.,0.,-1.));
#745=DIRECTION('',(-1.,0.,0.));
#746=AXIS2_PLACEMENT_3D('',#743,#744,#745);
#747=CIRCLE('',#746,5.);
#748=EDGE_CURVE('E418',#709,#740,#747,.T.);
#749=ORIENTED_EDGE('',*,*,#748,.F.);
#750=ORIENTED_EDGE('',*,*,#710,.T.);
#751=EDGE_LOOP('',(#734,#742,#749,#750));
#752=FACE_BOUND('',#751,.T.);
#753=ADVANCED_FACE('F624',(#752),#725,.T.);
#754=CARTESIAN_POINT('',(-50.,42.5,0.));
#755=DIRECTION('',(0.,0.,-1.));
#756=DIRECTION('',(-1.,0.,0.));
#757=AXIS2_PLACEMENT_3D('',#754,#755,#756);
#758=CYLINDRICAL_SURFACE('',#757,32.);
#759=ORIENTED_EDGE('',*,*,#741,.F.);
#760=CARTESIAN_POINT('',(-50.,42.5,0.));
#761=DIRECTION('',(0.,0.,-1.));
#762=DIRECTION('',(-1.,0.,0.));
#763=AXIS2_PLACEMENT_3D('',#760,#761,#762);
#764=CIRCLE('',#763,32.);
#765=CARTESIAN_POINT('',(-82.,42.5,0.));
#766=VERTEX_POINT('',#765);
#767=EDGE_CURVE('E254',#766,#732,#764,.T.);
#768=ORIENTED_EDGE('',*,*,#767,.F.);
#769=DIRECTION('',(0.,0.,1.));
#770=VECTOR('',#769,1.);
#771=CARTESIAN_POINT('',(-82.,42.5,0.));
#772=LINE('',#771,#770);
#773=CARTESIAN_POINT('',(-82.,42.5,-19.5));
#774=VERTEX_POINT('',#773);
#775=EDGE_CURVE('E240',#766,#774,#772,.F.);
#776=ORIENTED_EDGE('',*,*,#775,.T.);
#777=CARTESIAN_POINT('',(-50.,42.5,-19.5));
#778=DIRECTION('',(0.,0.,-1.));
#779=DIRECTION('',(-1.,0.,0.));
#780=AXIS2_PLACEMENT_3D('',#777,#778,#779);
#781=CIRCLE('',#780,32.);
#782=EDGE_CURVE('E416',#740,#774,#781,.F.);
#783=ORIENTED_EDGE('',*,*,#782,.F.);
#784=EDGE_LOOP('',(#759,#768,#776,#783));
#785=FACE_BOUND('',#784,.T.);
#786=ADVANCED_FACE('F621',(#785),#758,.F.);
#787=CARTESIAN_POINT('',(-82.,42.5,0.));
#788=DIRECTION('',(-1.,0.,0.));
#789=DIRECTION('',(0.,0.,1.));
#790=AXIS2_PLACEMENT_3D('',#787,#788,#789);
#791=PLANE('',#790);
#792=ORIENTED_EDGE('',*,*,#775,.F.);
#793=DIRECTION('',(0.,1.,0.));
#794=VECTOR('',#793,1.);
#795=CARTESIAN_POINT('',(-82.,84.,0.));
#796=LINE('',#795,#794);
#797=CARTESIAN_POINT('',(-82.,20.5,0.));
#798=VERTEX_POINT('',#797);
#799=EDGE_CURVE('E247',#798,#766,#796,.T.);
#800=ORIENTED_EDGE('',*,*,#799,.F.);
#801=DIRECTION('',(0.,0.,-1.));
#802=VECTOR('',#801,1.);
#803=CARTESIAN_POINT('',(-81.9999999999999,20.5,0.));
#804=LINE('',#803,#802);
#805=CARTESIAN_POINT('',(-82.,20.5,-19.5));
#806=VERTEX_POINT('',#805);
#807=EDGE_CURVE('E231',#806,#798,#804,.F.);
#808=ORIENTED_EDGE('',*,*,#807,.F.);
#809=DIRECTION('',(0.,1.,0.));
#810=VECTOR('',#809,1.);
#811=CARTESIAN_POINT('',(-82.,61.3926362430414,-19.5));
#812=LINE('',#811,#810);
#813=EDGE_CURVE('E415',#774,#806,#812,.F.);
#814=ORIENTED_EDGE('',*,*,#813,.F.);
#815=EDGE_LOOP('',(#792,#800,#808,#814));
#816=FACE_BOUND('',#815,.T.);
#817=ADVANCED_FACE('F252',(#816),#791,.F.);
#818=CARTESIAN_POINT('',(-86.,20.5,0.));
#819=DIRECTION('',(0.,0.,-1.));
#820=DIRECTION('',(-1.,0.,0.));
#821=AXIS2_PLACEMENT_3D('',#818,#819,#820);
#822=CYLINDRICAL_SURFACE('',#821,4.00000000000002);
#823=CARTESIAN_POINT('',(-86.,20.5,0.));
#824=DIRECTION('',(0.,0.,-1.));
#825=DIRECTION('',(-1.,0.,0.));
#826=AXIS2_PLACEMENT_3D('',#823,#824,#825);
#827=CIRCLE('',#826,4.00000000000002);
#828=CARTESIAN_POINT('',(-86.,16.5,0.));
#829=VERTEX_POINT('',#828);
#830=EDGE_CURVE('E234',#829,#798,#827,.F.);
#831=ORIENTED_EDGE('',*,*,#830,.F.);
#832=DIRECTION('',(0.,0.,1.));
#833=VECTOR('',#832,1.);
#834=CARTESIAN_POINT('',(-86.,16.5,0.));
#835=LINE('',#834,#833);
#836=CARTESIAN_POINT('',(-86.,16.5,-19.5));
#837=VERTEX_POINT('',#836);
#838=EDGE_CURVE('E224',#829,#837,#835,.F.);
#839=ORIENTED_EDGE('',*,*,#838,.T.);
#840=CARTESIAN_POINT('',(-86.,20.5,-19.5));
#841=DIRECTION('',(0.,0.,-1.));
#842=DIRECTION('',(-1.,0.,0.));
#843=AXIS2_PLACEMENT_3D('',#840,#841,#842);
#844=CIRCLE('',#843,4.00000000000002);
#845=EDGE_CURVE('E235',#806,#837,#844,.T.);
#846=ORIENTED_EDGE('',*,*,#845,.F.);
#847=ORIENTED_EDGE('',*,*,#807,.T.);
#848=EDGE_LOOP('',(#831,#839,#846,#847));
#849=FACE_BOUND('',#848,.T.);
#850=ADVANCED_FACE('F233',(#849),#822,.T.);
#851=CARTESIAN_POINT('',(50.,42.5,0.));
#852=DIRECTION('',(0.,0.,-1.));
#853=DIRECTION('',(-1.,0.,0.));
#854=AXIS2_PLACEMENT_3D('',#851,#852,#853);
#855=CYLINDRICAL_SURFACE('',#854,12.5);
#856=ORIENTED_EDGE('',*,*,#96,.T.);
#857=EDGE_LOOP('',(#856));
#858=FACE_BOUND('',#857,.T.);
#859=CARTESIAN_POINT('',(50.,42.5,-19.5));
#860=DIRECTION('',(0.,0.,-1.));
#861=DIRECTION('',(-1.,0.,0.));
#862=AXIS2_PLACEMENT_3D('',#859,#860,#861);
#863=CIRCLE('',#862,12.5);
#864=CARTESIAN_POINT('',(37.5,42.5,-19.5));
#865=VERTEX_POINT('',#864);
#866=EDGE_CURVE('E410',#865,#865,#863,.T.);
#867=ORIENTED_EDGE('',*,*,#866,.F.);
#868=EDGE_LOOP('',(#867));
#869=FACE_BOUND('',#868,.T.);
#870=ADVANCED_FACE('F612',(#858,#869),#855,.T.);
#871=CARTESIAN_POINT('',(-50.,42.5,0.));
#872=DIRECTION('',(0.,0.,-1.));
#873=DIRECTION('',(-1.,0.,0.));
#874=AXIS2_PLACEMENT_3D('',#871,#872,#873);
#875=CYLINDRICAL_SURFACE('',#874,12.5);
#876=ORIENTED_EDGE('',*,*,#116,.T.);
#877=EDGE_LOOP('',(#876));
#878=FACE_BOUND('',#877,.T.);
#879=CARTESIAN_POINT('',(-50.,42.5,-19.5));
#880=DIRECTION('',(0.,0.,-1.));
#881=DIRECTION('',(-1.,0.,0.));
#882=AXIS2_PLACEMENT_3D('',#879,#880,#881);
#883=CIRCLE('',#882,12.5);
#884=CARTESIAN_POINT('',(-62.5,42.5,-19.5));
#885=VERTEX_POINT('',#884);
#886=EDGE_CURVE('E407',#885,#885,#883,.T.);
#887=ORIENTED_EDGE('',*,*,#886,.F.);
#888=EDGE_LOOP('',(#887));
#889=FACE_BOUND('',#888,.T.);
#890=ADVANCED_FACE('F608',(#878,#889),#875,.T.);
#891=CARTESIAN_POINT('',(0.,121.3,0.));
#892=DIRECTION('',(0.,0.,-1.));
#893=DIRECTION('',(-1.,0.,0.));
#894=AXIS2_PLACEMENT_3D('',#891,#892,#893);
#895=CYLINDRICAL_SURFACE('',#894,12.5);
#896=CARTESIAN_POINT('',(0.,121.3,-19.5));
#897=DIRECTION('',(0.,0.,-1.));
#898=DIRECTION('',(-1.,0.,0.));
#899=AXIS2_PLACEMENT_3D('',#896,#897,#898);
#900=CIRCLE('',#899,12.5);
#901=CARTESIAN_POINT('',(-12.5,121.3,-19.5));
#902=VERTEX_POINT('',#901);
#903=EDGE_CURVE('E273',#902,#902,#900,.T.);
#904=ORIENTED_EDGE('',*,*,#903,.F.);
#905=EDGE_LOOP('',(#904));
#906=FACE_BOUND('',#905,.T.);
#907=CARTESIAN_POINT('',(0.,121.3,-6.75));
#908=DIRECTION('',(0.,0.,-1.));
#909=DIRECTION('',(-1.,0.,0.));
#910=AXIS2_PLACEMENT_3D('',#907,#908,#909);
#911=CIRCLE('',#910,12.5);
#912=CARTESIAN_POINT('',(-12.5,121.3,-6.75));
#913=VERTEX_POINT('',#912);
#914=EDGE_CURVE('E465',#913,#913,#911,.T.);
#915=ORIENTED_EDGE('',*,*,#914,.T.);
#916=EDGE_LOOP('',(#915));
#917=FACE_BOUND('',#916,.T.);
#918=ADVANCED_FACE('F605',(#906,#917),#895,.T.);
#919=CARTESIAN_POINT('',(-86.,16.5,0.));
#920=DIRECTION('',(0.,1.,0.));
#921=DIRECTION('',(0.,0.,1.));
#922=AXIS2_PLACEMENT_3D('',#919,#920,#921);
#923=PLANE('',#922);
#924=ORIENTED_EDGE('',*,*,#838,.F.);
#925=DIRECTION('',(1.,0.,0.));
#926=VECTOR('',#925,1.);
#927=CARTESIAN_POINT('',(0.,16.5,0.));
#928=LINE('',#927,#926);
#929=CARTESIAN_POINT('',(-90.,16.5,0.));
#930=VERTEX_POINT('',#929);
#931=EDGE_CURVE('E250',#930,#829,#928,.T.);
#932=ORIENTED_EDGE('',*,*,#931,.F.);
#933=DIRECTION('',(0.,0.,1.));
#934=VECTOR('',#933,1.);
#935=CARTESIAN_POINT('',(-90.,16.5,0.));
#936=LINE('',#935,#934);
#937=CARTESIAN_POINT('',(-89.9999999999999,16.5,-19.5));
#938=VERTEX_POINT('',#937);
#939=EDGE_CURVE('E272',#938,#930,#936,.T.);
#940=ORIENTED_EDGE('',*,*,#939,.F.);
#941=DIRECTION('',(1.,0.,0.));
#942=VECTOR('',#941,1.);
#943=CARTESIAN_POINT('',(0.,16.5,-19.5));
#944=LINE('',#943,#942);
#945=EDGE_CURVE('E413',#837,#938,#944,.F.);
#946=ORIENTED_EDGE('',*,*,#945,.F.);
#947=EDGE_LOOP('',(#924,#932,#940,#946));
#948=FACE_BOUND('',#947,.T.);
#949=ADVANCED_FACE('F601',(#948),#923,.F.);
#950=CARTESIAN_POINT('',(50.,3.5,0.));
#951=DIRECTION('',(-1.,0.,0.));
#952=DIRECTION('',(0.,0.,1.));
#953=AXIS2_PLACEMENT_3D('',#950,#951,#952);
#954=PLANE('',#953);
#955=ORIENTED_EDGE('',*,*,#476,.F.);
#956=DIRECTION('',(0.,1.,0.));
#957=VECTOR('',#956,1.);
#958=CARTESIAN_POINT('',(50.,84.,0.));
#959=LINE('',#958,#957);
#960=CARTESIAN_POINT('',(50.,1.5,0.));
#961=VERTEX_POINT('',#960);
#962=EDGE_CURVE('E350',#961,#467,#959,.T.);
#963=ORIENTED_EDGE('',*,*,#962,.F.);
#964=DIRECTION('',(0.,0.,-1.));
#965=VECTOR('',#964,1.);
#966=CARTESIAN_POINT('',(50.,1.5,0.));
#967=LINE('',#966,#965);
#968=CARTESIAN_POINT('',(50.,1.5,-19.5));
#969=VERTEX_POINT('',#968);
#970=EDGE_CURVE('E355',#969,#961,#967,.F.);
#971=ORIENTED_EDGE('',*,*,#970,.F.);
#972=DIRECTION('',(0.,1.,0.));
#973=VECTOR('',#972,1.);
#974=CARTESIAN_POINT('',(50.,61.3926362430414,-19.5));
#975=LINE('',#974,#973);
#976=EDGE_CURVE('E313',#475,#969,#975,.F.);
#977=ORIENTED_EDGE('',*,*,#976,.F.);
#978=EDGE_LOOP('',(#955,#963,#971,#977));
#979=FACE_BOUND('',#978,.T.);
#980=ADVANCED_FACE('F597',(#979),#954,.F.);
#981=CARTESIAN_POINT('',(-50.,1.5,0.));
#982=DIRECTION('',(1.,0.,0.));
#983=DIRECTION('',(0.,0.,-1.));
#984=AXIS2_PLACEMENT_3D('',#981,#982,#983);
#985=PLANE('',#984);
#986=DIRECTION('',(0.,0.,-1.));
#987=VECTOR('',#986,1.);
#988=CARTESIAN_POINT('',(-50.,1.5,0.));
#989=LINE('',#988,#987);
#990=CARTESIAN_POINT('',(-50.,1.5,0.));
#991=VERTEX_POINT('',#990);
#992=CARTESIAN_POINT('',(-50.,1.5,-19.5));
#993=VERTEX_POINT('',#992);
#994=EDGE_CURVE('E343',#991,#993,#989,.T.);
#995=ORIENTED_EDGE('',*,*,#994,.F.);
#996=DIRECTION('',(0.,1.,0.));
#997=VECTOR('',#996,1.);
#998=CARTESIAN_POINT('',(-50.,84.,0.));
#999=LINE('',#998,#997);
#1000=EDGE_CURVE('E340',#201,#991,#999,.F.);
#1001=ORIENTED_EDGE('',*,*,#1000,.F.);
#1002=ORIENTED_EDGE('',*,*,#202,.F.);
#1003=DIRECTION('',(0.,1.,0.));
#1004=VECTOR('',#1003,1.);
#1005=CARTESIAN_POINT('',(-50.,61.3926362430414,-19.5));
#1006=LINE('',#1005,#1004);
#1007=EDGE_CURVE('E336',#993,#199,#1006,.T.);
#1008=ORIENTED_EDGE('',*,*,#1007,.F.);
#1009=EDGE_LOOP('',(#995,#1001,#1002,#1008));
#1010=FACE_BOUND('',#1009,.T.);
#1011=ADVANCED_FACE('F593',(#1010),#985,.F.);
#1012=CARTESIAN_POINT('',(89.9999999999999,16.5,0.));
#1013=DIRECTION('',(0.,1.,0.));
#1014=DIRECTION('',(0.,0.,1.));
#1015=AXIS2_PLACEMENT_3D('',#1012,#1013,#1014);
#1016=PLANE('',#1015);
#1017=DIRECTION('',(0.,0.,-1.));
#1018=VECTOR('',#1017,1.);
#1019=CARTESIAN_POINT('',(89.9999999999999,16.5,0.));
#1020=LINE('',#1019,#1018);
#1021=CARTESIAN_POINT('',(89.9999999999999,16.5,0.));
#1022=VERTEX_POINT('',#1021);
#1023=CARTESIAN_POINT('',(89.9999999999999,16.5,-19.5));
#1024=VERTEX_POINT('',#1023);
#1025=EDGE_CURVE('E302',#1022,#1024,#1020,.T.);
#1026=ORIENTED_EDGE('',*,*,#1025,.F.);
#1027=DIRECTION('',(1.,0.,0.));
#1028=VECTOR('',#1027,1.);
#1029=CARTESIAN_POINT('',(0.,16.5,0.));
#1030=LINE('',#1029,#1028);
#1031=EDGE_CURVE('E263',#500,#1022,#1030,.T.);
#1032=ORIENTED_EDGE('',*,*,#1031,.F.);
#1033=ORIENTED_EDGE('',*,*,#524,.F.);
#1034=DIRECTION('',(1.,0.,0.));
#1035=VECTOR('',#1034,1.);
#1036=CARTESIAN_POINT('',(0.,16.5,-19.5));
#1037=LINE('',#1036,#1035);
#1038=EDGE_CURVE('E315',#1024,#517,#1037,.F.);
#1039=ORIENTED_EDGE('',*,*,#1038,.F.);
#1040=EDGE_LOOP('',(#1026,#1032,#1033,#1039));
#1041=FACE_BOUND('',#1040,.T.);
#1042=ADVANCED_FACE('F589',(#1041),#1016,.F.);
#1043=CARTESIAN_POINT('',(0.,84.,0.));
#1044=DIRECTION('',(0.,0.,1.));
#1045=DIRECTION('',(1.,0.,0.));
#1046=AXIS2_PLACEMENT_3D('',#1043,#1044,#1045);
#1047=PLANE('',#1046);
#1048=ORIENTED_EDGE('',*,*,#173,.T.);
#1049=EDGE_LOOP('',(#1048));
#1050=FACE_BOUND('',#1049,.T.);
#1051=ORIENTED_EDGE('',*,*,#133,.T.);
#1052=EDGE_LOOP('',(#1051));
#1053=FACE_BOUND('',#1052,.T.);
#1054=ORIENTED_EDGE('',*,*,#541,.T.);
#1055=ORIENTED_EDGE('',*,*,#501,.T.);
#1056=ORIENTED_EDGE('',*,*,#1031,.T.);
#1057=DIRECTION('',(0.,1.,0.));
#1058=VECTOR('',#1057,1.);
#1059=CARTESIAN_POINT('',(89.9999999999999,1.5,0.));
#1060=LINE('',#1059,#1058);
#1061=CARTESIAN_POINT('',(90.,164.,0.));
#1062=VERTEX_POINT('',#1061);
#1063=EDGE_CURVE('E361',#1062,#1022,#1060,.F.);
#1064=ORIENTED_EDGE('',*,*,#1063,.F.);
#1065=DIRECTION('',(-0.707106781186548,0.707106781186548,0.));
#1066=VECTOR('',#1065,1.);
#1067=CARTESIAN_POINT('',(88.75,165.25,0.));
#1068=LINE('',#1067,#1066);
#1069=CARTESIAN_POINT('',(87.5,166.5,0.));
#1070=VERTEX_POINT('',#1069);
#1071=EDGE_CURVE('E363',#1070,#1062,#1068,.F.);
#1072=ORIENTED_EDGE('',*,*,#1071,.F.);
#1073=DIRECTION('',(1.,0.,0.));
#1074=VECTOR('',#1073,1.);
#1075=CARTESIAN_POINT('',(90.,166.5,0.));
#1076=LINE('',#1075,#1074);
#1077=CARTESIAN_POINT('',(-87.5,166.5,0.));
#1078=VERTEX_POINT('',#1077);
#1079=EDGE_CURVE('E778',#1078,#1070,#1076,.T.);
#1080=ORIENTED_EDGE('',*,*,#1079,.F.);
#1081=DIRECTION('',(-0.707106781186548,-0.707106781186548,0.));
#1082=VECTOR('',#1081,1.);
#1083=CARTESIAN_POINT('',(-88.75,165.25,0.));
#1084=LINE('',#1083,#1082);
#1085=CARTESIAN_POINT('',(-90.,164.,0.));
#1086=VERTEX_POINT('',#1085);
#1087=EDGE_CURVE('E788',#1086,#1078,#1084,.F.);
#1088=ORIENTED_EDGE('',*,*,#1087,.F.);
#1089=DIRECTION('',(0.,1.,0.));
#1090=VECTOR('',#1089,1.);
#1091=CARTESIAN_POINT('',(-90.,166.5,0.));
#1092=LINE('',#1091,#1090);
#1093=EDGE_CURVE('E274',#930,#1086,#1092,.T.);
#1094=ORIENTED_EDGE('',*,*,#1093,.F.);
#1095=ORIENTED_EDGE('',*,*,#931,.T.);
#1096=ORIENTED_EDGE('',*,*,#830,.T.);
#1097=ORIENTED_EDGE('',*,*,#799,.T.);
#1098=ORIENTED_EDGE('',*,*,#767,.T.);
#1099=ORIENTED_EDGE('',*,*,#733,.T.);
#1100=ORIENTED_EDGE('',*,*,#702,.T.);
#1101=ORIENTED_EDGE('',*,*,#670,.T.);
#1102=ORIENTED_EDGE('',*,*,#638,.T.);
#1103=ORIENTED_EDGE('',*,*,#605,.T.);
#1104=ORIENTED_EDGE('',*,*,#573,.T.);
#1105=EDGE_LOOP('',(#1054,#1055,#1056,#1064,#1072,#1080,#1088,#1094,#1095,#1096,#1097,#1098,
#1099,#1100,#1101,#1102,#1103,#1104));
#1106=FACE_BOUND('',#1105,.T.);
#1107=ADVANCED_FACE('F245',(#1050,#1053,#1106),#1047,.T.);
#1108=CARTESIAN_POINT('',(0.,121.3,-6.75));
#1109=DIRECTION('',(0.,0.,-1.));
#1110=DIRECTION('',(-1.,0.,0.));
#1111=AXIS2_PLACEMENT_3D('',#1108,#1109,#1110);
#1112=PLANE('',#1111);
#1113=CARTESIAN_POINT('',(0.,121.3,-6.75));
#1114=DIRECTION('',(0.,0.,-1.));
#1115=DIRECTION('',(-1.,0.,0.));
#1116=AXIS2_PLACEMENT_3D('',#1113,#1114,#1115);
#1117=CIRCLE('',#1116,9.);
#1118=CARTESIAN_POINT('',(-8.99999999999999,121.3,-6.75));
#1119=VERTEX_POINT('',#1118);
#1120=EDGE_CURVE('E402',#1119,#1119,#1117,.T.);
#1121=ORIENTED_EDGE('',*,*,#1120,.T.);
#1122=EDGE_LOOP('',(#1121));
#1123=FACE_BOUND('',#1122,.T.);
#1124=ORIENTED_EDGE('',*,*,#914,.F.);
#1125=EDGE_LOOP('',(#1124));
#1126=FACE_BOUND('',#1125,.T.);
#1127=ADVANCED_FACE('F582',(#1123,#1126),#1112,.F.);
#1128=CARTESIAN_POINT('',(57.6499999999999,50.15,-21.25));
#1129=DIRECTION('',(0.,0.,1.));
#1130=DIRECTION('',(-1.,0.,0.));
#1131=AXIS2_PLACEMENT_3D('',#1128,#1129,#1130);
#1132=PLANE('',#1131);
#1133=ORIENTED_EDGE('',*,*,#156,.F.);
#1134=EDGE_LOOP('',(#1133));
#1135=FACE_BOUND('',#1134,.T.);
#1136=CARTESIAN_POINT('',(50.,42.5,-21.25));
#1137=DIRECTION('',(0.,0.,1.));
#1138=DIRECTION('',(1.,0.,0.));
#1139=AXIS2_PLACEMENT_3D('',#1136,#1137,#1138);
#1140=CIRCLE('',#1139,7.5);
#1141=CARTESIAN_POINT('',(57.5,42.5,-21.25));
#1142=VERTEX_POINT('',#1141);
#1143=EDGE_CURVE('E399',#1142,#1142,#1140,.F.);
#1144=ORIENTED_EDGE('',*,*,#1143,.T.);
#1145=EDGE_LOOP('',(#1144));
#1146=FACE_BOUND('',#1145,.T.);
#1147=ADVANCED_FACE('F585',(#1135,#1146),#1132,.F.);
#1148=CARTESIAN_POINT('',(87.6499999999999,154.15,-21.25));
#1149=DIRECTION('',(0.,0.,1.));
#1150=DIRECTION('',(-1.,0.,0.));
#1151=AXIS2_PLACEMENT_3D('',#1148,#1149,#1150);
#1152=PLANE('',#1151);
#1153=ORIENTED_EDGE('',*,*,#184,.F.);
#1154=EDGE_LOOP('',(#1153));
#1155=FACE_BOUND('',#1154,.T.);
#1156=CARTESIAN_POINT('',(79.9999999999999,146.5,-21.25));
#1157=DIRECTION('',(0.,0.,1.));
#1158=DIRECTION('',(1.,0.,0.));
#1159=AXIS2_PLACEMENT_3D('',#1156,#1157,#1158);
#1160=CIRCLE('',#1159,7.49999999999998);
#1161=CARTESIAN_POINT('',(87.4999999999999,146.5,-21.25));
#1162=VERTEX_POINT('',#1161);
#1163=EDGE_CURVE('E396',#1162,#1162,#1160,.F.);
#1164=ORIENTED_EDGE('',*,*,#1163,.T.);
#1165=EDGE_LOOP('',(#1164));
#1166=FACE_BOUND('',#1165,.T.);
#1167=ADVANCED_FACE('F580',(#1155,#1166),#1152,.F.);
#1168=CARTESIAN_POINT('',(0.,84.,0.));
#1169=DIRECTION('',(0.,0.,1.));
#1170=DIRECTION('',(1.,0.,0.));
#1171=AXIS2_PLACEMENT_3D('',#1168,#1169,#1170);
#1172=PLANE('',#1171);
#1173=CARTESIAN_POINT('',(-22.4999999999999,11.,0.));
#1174=DIRECTION('',(0.,0.,-1.));
#1175=DIRECTION('',(-1.,0.,0.));
#1176=AXIS2_PLACEMENT_3D('',#1173,#1174,#1175);
#1177=CIRCLE('',#1176,4.);
#1178=CARTESIAN_POINT('',(-26.4999999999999,11.,0.));
#1179=VERTEX_POINT('',#1178);
#1180=EDGE_CURVE('E387',#1179,#1179,#1177,.T.);
#1181=ORIENTED_EDGE('',*,*,#1180,.T.);
#1182=EDGE_LOOP('',(#1181));
#1183=FACE_BOUND('',#1182,.T.);
#1184=CARTESIAN_POINT('',(22.5000000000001,11.,0.));
#1185=DIRECTION('',(0.,0.,-1.));
#1186=DIRECTION('',(-1.,0.,0.));
#1187=AXIS2_PLACEMENT_3D('',#1184,#1185,#1186);
#1188=CIRCLE('',#1187,4.);
#1189=CARTESIAN_POINT('',(18.5000000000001,11.,0.));
#1190=VERTEX_POINT('',#1189);
#1191=EDGE_CURVE('E390',#1190,#1190,#1188,.T.);
#1192=ORIENTED_EDGE('',*,*,#1191,.T.);
#1193=EDGE_LOOP('',(#1192));
#1194=FACE_BOUND('',#1193,.T.);
#1195=ORIENTED_EDGE('',*,*,#1000,.T.);
#1196=DIRECTION('',(1.,0.,0.));
#1197=VECTOR('',#1196,1.);
#1198=CARTESIAN_POINT('',(-89.9999999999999,1.5,0.));
#1199=LINE('',#1198,#1197);
#1200=EDGE_CURVE('E346',#961,#991,#1199,.F.);
#1201=ORIENTED_EDGE('',*,*,#1200,.F.);
#1202=ORIENTED_EDGE('',*,*,#962,.T.);
#1203=ORIENTED_EDGE('',*,*,#468,.T.);
#1204=ORIENTED_EDGE('',*,*,#436,.T.);
#1205=ORIENTED_EDGE('',*,*,#404,.T.);
#1206=ORIENTED_EDGE('',*,*,#371,.T.);
#1207=ORIENTED_EDGE('',*,*,#339,.T.);
#1208=ORIENTED_EDGE('',*,*,#305,.T.);
#1209=ORIENTED_EDGE('',*,*,#274,.T.);
#1210=ORIENTED_EDGE('',*,*,#242,.T.);
#1211=ORIENTED_EDGE('',*,*,#210,.T.);
#1212=EDGE_LOOP('',(#1195,#1201,#1202,#1203,#1204,#1205,#1206,#1207,#1208,#1209,#1210,#1211));
#1213=FACE_BOUND('',#1212,.T.);
#1214=ADVANCED_FACE('F576',(#1183,#1194,#1213),#1172,.T.);
#1215=CARTESIAN_POINT('',(0.,61.3926362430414,-19.5));
#1216=DIRECTION('',(0.,0.,1.));
#1217=DIRECTION('',(1.,0.,0.));
#1218=AXIS2_PLACEMENT_3D('',#1215,#1216,#1217);
#1219=PLANE('',#1218);
#1220=CARTESIAN_POINT('',(67.5000000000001,11.,-19.5));
#1221=DIRECTION('',(0.,0.,-1.));
#1222=DIRECTION('',(-1.,0.,0.));
#1223=AXIS2_PLACEMENT_3D('',#1220,#1221,#1222);
#1224=CIRCLE('',#1223,4.);
#1225=CARTESIAN_POINT('',(63.5000000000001,11.,-19.5));
#1226=VERTEX_POINT('',#1225);
#1227=EDGE_CURVE('E393',#1226,#1226,#1224,.T.);
#1228=ORIENTED_EDGE('',*,*,#1227,.T.);
#1229=EDGE_LOOP('',(#1228));
#1230=FACE_BOUND('',#1229,.T.);
#1231=CARTESIAN_POINT('',(-67.4999999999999,11.,-19.5));
#1232=DIRECTION('',(0.,0.,-1.));
#1233=DIRECTION('',(-1.,0.,0.));
#1234=AXIS2_PLACEMENT_3D('',#1231,#1232,#1233);
#1235=CIRCLE('',#1234,4.);
#1236=CARTESIAN_POINT('',(-71.5,11.,-19.5));
#1237=VERTEX_POINT('',#1236);
#1238=EDGE_CURVE('E383',#1237,#1237,#1235,.T.);
#1239=ORIENTED_EDGE('',*,*,#1238,.T.);
#1240=EDGE_LOOP('',(#1239));
#1241=FACE_BOUND('',#1240,.T.);
#1242=ORIENTED_EDGE('',*,*,#903,.T.);
#1243=EDGE_LOOP('',(#1242));
#1244=FACE_BOUND('',#1243,.T.);
#1245=ORIENTED_EDGE('',*,*,#886,.T.);
#1246=EDGE_LOOP('',(#1245));
#1247=FACE_BOUND('',#1246,.T.);
#1248=ORIENTED_EDGE('',*,*,#866,.T.);
#1249=EDGE_LOOP('',(#1248));
#1250=FACE_BOUND('',#1249,.T.);
#1251=DIRECTION('',(0.,1.,0.));
#1252=VECTOR('',#1251,1.);
#1253=CARTESIAN_POINT('',(-90.,166.5,-19.5));
#1254=LINE('',#1253,#1252);
#1255=CARTESIAN_POINT('',(-90.,1.5,-19.5));
#1256=VERTEX_POINT('',#1255);
#1257=EDGE_CURVE('E269',#1256,#938,#1254,.T.);
#1258=ORIENTED_EDGE('',*,*,#1257,.F.);
#1259=DIRECTION('',(1.,0.,0.));
#1260=VECTOR('',#1259,1.);
#1261=CARTESIAN_POINT('',(-89.9999999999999,1.5,-19.5));
#1262=LINE('',#1261,#1260);
#1263=EDGE_CURVE('E345',#993,#1256,#1262,.F.);
#1264=ORIENTED_EDGE('',*,*,#1263,.F.);
#1265=ORIENTED_EDGE('',*,*,#1007,.T.);
#1266=ORIENTED_EDGE('',*,*,#224,.T.);
#1267=ORIENTED_EDGE('',*,*,#257,.T.);
#1268=ORIENTED_EDGE('',*,*,#288,.T.);
#1269=ORIENTED_EDGE('',*,*,#320,.T.);
#1270=ORIENTED_EDGE('',*,*,#354,.T.);
#1271=ORIENTED_EDGE('',*,*,#386,.T.);
#1272=ORIENTED_EDGE('',*,*,#418,.T.);
#1273=ORIENTED_EDGE('',*,*,#451,.T.);
#1274=ORIENTED_EDGE('',*,*,#482,.T.);
#1275=ORIENTED_EDGE('',*,*,#976,.T.);
#1276=DIRECTION('',(1.,0.,0.));
#1277=VECTOR('',#1276,1.);
#1278=CARTESIAN_POINT('',(-89.9999999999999,1.5,-19.5));
#1279=LINE('',#1278,#1277);
#1280=CARTESIAN_POINT('',(89.9999999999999,1.5,-19.5));
#1281=VERTEX_POINT('',#1280);
#1282=EDGE_CURVE('E357',#1281,#969,#1279,.F.);
#1283=ORIENTED_EDGE('',*,*,#1282,.F.);
#1284=DIRECTION('',(0.,1.,0.));
#1285=VECTOR('',#1284,1.);
#1286=CARTESIAN_POINT('',(89.9999999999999,1.5,-19.5));
#1287=LINE('',#1286,#1285);
#1288=EDGE_CURVE('E304',#1024,#1281,#1287,.F.);
#1289=ORIENTED_EDGE('',*,*,#1288,.F.);
#1290=ORIENTED_EDGE('',*,*,#1038,.T.);
#1291=ORIENTED_EDGE('',*,*,#518,.T.);
#1292=ORIENTED_EDGE('',*,*,#555,.T.);
#1293=ORIENTED_EDGE('',*,*,#588,.T.);
#1294=ORIENTED_EDGE('',*,*,#620,.T.);
#1295=ORIENTED_EDGE('',*,*,#652,.T.);
#1296=ORIENTED_EDGE('',*,*,#685,.T.);
#1297=ORIENTED_EDGE('',*,*,#716,.T.);
#1298=ORIENTED_EDGE('',*,*,#748,.T.);
#1299=ORIENTED_EDGE('',*,*,#782,.T.);
#1300=ORIENTED_EDGE('',*,*,#813,.T.);
#1301=ORIENTED_EDGE('',*,*,#845,.T.);
#1302=ORIENTED_EDGE('',*,*,#945,.T.);
#1303=EDGE_LOOP('',(#1258,#1264,#1265,#1266,#1267,#1268,#1269,#1270,#1271,#1272,#1273,#1274,
#1275,#1283,#1289,#1290,#1291,#1292,#1293,#1294,#1295,#1296,#1297,#1298,#1299,#1300,#1301,#1302));
#1304=FACE_BOUND('',#1303,.T.);
#1305=ADVANCED_FACE('F572',(#1230,#1241,#1244,#1247,#1250,#1304),#1219,.T.);
#1306=CARTESIAN_POINT('',(-90.,166.5,0.));
#1307=DIRECTION('',(-1.,0.,0.));
#1308=DIRECTION('',(0.,0.,1.));
#1309=AXIS2_PLACEMENT_3D('',#1306,#1307,#1308);
#1310=PLANE('',#1309);
#1311=DIRECTION('',(0.,1.,0.));
#1312=VECTOR('',#1311,1.);
#1313=CARTESIAN_POINT('',(-90.,84.,-30.25));
#1314=LINE('',#1313,#1312);
#1315=CARTESIAN_POINT('',(-90.,164.,-30.25));
#1316=VERTEX_POINT('',#1315);
#1317=CARTESIAN_POINT('',(-90.,1.5,-30.25));
#1318=VERTEX_POINT('',#1317);
#1319=EDGE_CURVE('E386',#1316,#1318,#1314,.F.);
#1320=ORIENTED_EDGE('',*,*,#1319,.T.);
#1321=DIRECTION('',(0.,0.,-1.));
#1322=VECTOR('',#1321,1.);
#1323=CARTESIAN_POINT('',(-89.9999999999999,1.5,0.));
#1324=LINE('',#1323,#1322);
#1325=EDGE_CURVE('E305',#1256,#1318,#1324,.T.);
#1326=ORIENTED_EDGE('',*,*,#1325,.F.);
#1327=ORIENTED_EDGE('',*,*,#1257,.T.);
#1328=ORIENTED_EDGE('',*,*,#939,.T.);
#1329=ORIENTED_EDGE('',*,*,#1093,.T.);
#1330=DIRECTION('',(0.,0.,1.));
#1331=VECTOR('',#1330,1.);
#1332=CARTESIAN_POINT('',(-90.,164.,0.));
#1333=LINE('',#1332,#1331);
#1334=EDGE_CURVE('E785',#1316,#1086,#1333,.T.);
#1335=ORIENTED_EDGE('',*,*,#1334,.F.);
#1336=EDGE_LOOP('',(#1320,#1326,#1327,#1328,#1329,#1335));
#1337=FACE_BOUND('',#1336,.T.);
#1338=ADVANCED_FACE('F568',(#1337),#1310,.T.);
#1339=CARTESIAN_POINT('',(-89.9999999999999,1.5,0.));
#1340=DIRECTION('',(0.,-1.,0.));
#1341=DIRECTION('',(0.,0.,-1.));
#1342=AXIS2_PLACEMENT_3D('',#1339,#1340,#1341);
#1343=PLANE('',#1342);
#1344=DIRECTION('',(1.,0.,0.));
#1345=VECTOR('',#1344,1.);
#1346=CARTESIAN_POINT('',(0.,1.5,-30.25));
#1347=LINE('',#1346,#1345);
#1348=CARTESIAN_POINT('',(89.9999999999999,1.5,-30.25));
#1349=VERTEX_POINT('',#1348);
#1350=EDGE_CURVE('E799',#1318,#1349,#1347,.T.);
#1351=ORIENTED_EDGE('',*,*,#1350,.T.);
#1352=DIRECTION('',(0.,0.,-1.));
#1353=VECTOR('',#1352,1.);
#1354=CARTESIAN_POINT('',(89.9999999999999,1.5,0.));
#1355=LINE('',#1354,#1353);
#1356=EDGE_CURVE('E307',#1281,#1349,#1355,.T.);
#1357=ORIENTED_EDGE('',*,*,#1356,.F.);
#1358=ORIENTED_EDGE('',*,*,#1282,.T.);
#1359=ORIENTED_EDGE('',*,*,#970,.T.);
#1360=ORIENTED_EDGE('',*,*,#1200,.T.);
#1361=ORIENTED_EDGE('',*,*,#994,.T.);
#1362=ORIENTED_EDGE('',*,*,#1263,.T.);
#1363=ORIENTED_EDGE('',*,*,#1325,.T.);
#1364=EDGE_LOOP('',(#1351,#1357,#1358,#1359,#1360,#1361,#1362,#1363));
#1365=FACE_BOUND('',#1364,.T.);
#1366=ADVANCED_FACE('F564',(#1365),#1343,.T.);
#1367=CARTESIAN_POINT('',(89.9999999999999,1.5,0.));
#1368=DIRECTION('',(1.,0.,0.));
#1369=DIRECTION('',(0.,0.,-1.));
#1370=AXIS2_PLACEMENT_3D('',#1367,#1368,#1369);
#1371=PLANE('',#1370);
#1372=DIRECTION('',(0.,0.,1.));
#1373=VECTOR('',#1372,1.);
#1374=CARTESIAN_POINT('',(90.,164.,0.));
#1375=LINE('',#1374,#1373);
#1376=CARTESIAN_POINT('',(90.,164.,-30.25));
#1377=VERTEX_POINT('',#1376);
#1378=EDGE_CURVE('E773',#1062,#1377,#1375,.F.);
#1379=ORIENTED_EDGE('',*,*,#1378,.F.);
#1380=ORIENTED_EDGE('',*,*,#1063,.T.);
#1381=ORIENTED_EDGE('',*,*,#1025,.T.);
#1382=ORIENTED_EDGE('',*,*,#1288,.T.);
#1383=ORIENTED_EDGE('',*,*,#1356,.T.);
#1384=DIRECTION('',(0.,1.,0.));
#1385=VECTOR('',#1384,1.);
#1386=CARTESIAN_POINT('',(89.9999999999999,84.,-30.25));
#1387=LINE('',#1386,#1385);
#1388=EDGE_CURVE('E795',#1349,#1377,#1387,.T.);
#1389=ORIENTED_EDGE('',*,*,#1388,.T.);
#1390=EDGE_LOOP('',(#1379,#1380,#1381,#1382,#1383,#1389));
#1391=FACE_BOUND('',#1390,.T.);
#1392=ADVANCED_FACE('F560',(#1391),#1371,.T.);
#1393=CARTESIAN_POINT('',(88.75,165.25,0.));
#1394=DIRECTION('',(0.707106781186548,0.707106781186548,0.));
#1395=DIRECTION('',(-0.707106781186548,0.707106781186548,0.));
#1396=AXIS2_PLACEMENT_3D('',#1393,#1394,#1395);
#1397=PLANE('',#1396);
#1398=ORIENTED_EDGE('',*,*,#1071,.T.);
#1399=ORIENTED_EDGE('',*,*,#1378,.T.);
#1400=DIRECTION('',(-0.707106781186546,0.707106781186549,0.));
#1401=VECTOR('',#1400,1.);
#1402=CARTESIAN_POINT('',(90.,164.,-30.25));
#1403=LINE('',#1402,#1401);
#1404=CARTESIAN_POINT('',(87.5,166.5,-30.25));
#1405=VERTEX_POINT('',#1404);
#1406=EDGE_CURVE('E782',#1377,#1405,#1403,.T.);
#1407=ORIENTED_EDGE('',*,*,#1406,.T.);
#1408=DIRECTION('',(0.,0.,1.));
#1409=VECTOR('',#1408,1.);
#1410=CARTESIAN_POINT('',(87.5,166.5,0.));
#1411=LINE('',#1410,#1409);
#1412=EDGE_CURVE('E780',#1070,#1405,#1411,.F.);
#1413=ORIENTED_EDGE('',*,*,#1412,.F.);
#1414=EDGE_LOOP('',(#1398,#1399,#1407,#1413));
#1415=FACE_BOUND('',#1414,.T.);
#1416=ADVANCED_FACE('F556',(#1415),#1397,.T.);
#1417=CARTESIAN_POINT('',(90.,166.5,0.));
#1418=DIRECTION('',(0.,1.,0.));
#1419=DIRECTION('',(0.,0.,1.));
#1420=AXIS2_PLACEMENT_3D('',#1417,#1418,#1419);
#1421=PLANE('',#1420);
#1422=ORIENTED_EDGE('',*,*,#1412,.T.);
#1423=DIRECTION('',(1.,0.,0.));
#1424=VECTOR('',#1423,1.);
#1425=CARTESIAN_POINT('',(0.,166.5,-30.25));
#1426=LINE('',#1425,#1424);
#1427=CARTESIAN_POINT('',(-87.5,166.5,-30.25));
#1428=VERTEX_POINT('',#1427);
#1429=EDGE_CURVE('E796',#1405,#1428,#1426,.F.);
#1430=ORIENTED_EDGE('',*,*,#1429,.T.);
#1431=DIRECTION('',(0.,0.,1.));
#1432=VECTOR('',#1431,1.);
#1433=CARTESIAN_POINT('',(-87.5,166.5,0.));
#1434=LINE('',#1433,#1432);
#1435=EDGE_CURVE('E35',#1078,#1428,#1434,.F.);
#1436=ORIENTED_EDGE('',*,*,#1435,.F.);
#1437=ORIENTED_EDGE('',*,*,#1079,.T.);
#1438=EDGE_LOOP('',(#1422,#1430,#1436,#1437));
#1439=FACE_BOUND('',#1438,.T.);
#1440=ADVANCED_FACE('F553',(#1439),#1421,.T.);
#1441=CARTESIAN_POINT('',(-88.75,165.25,0.));
#1442=DIRECTION('',(-0.707106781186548,0.707106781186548,0.));
#1443=DIRECTION('',(-0.707106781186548,-0.707106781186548,0.));
#1444=AXIS2_PLACEMENT_3D('',#1441,#1442,#1443);
#1445=PLANE('',#1444);
#1446=ORIENTED_EDGE('',*,*,#1087,.T.);
#1447=ORIENTED_EDGE('',*,*,#1435,.T.);
#1448=DIRECTION('',(-0.707106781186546,-0.707106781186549,0.));
#1449=VECTOR('',#1448,1.);
#1450=CARTESIAN_POINT('',(-87.5,166.5,-30.25));
#1451=LINE('',#1450,#1449);
#1452=EDGE_CURVE('E382',#1428,#1316,#1451,.T.);
#1453=ORIENTED_EDGE('',*,*,#1452,.T.);
#1454=ORIENTED_EDGE('',*,*,#1334,.T.);
#1455=EDGE_LOOP('',(#1446,#1447,#1453,#1454));
#1456=FACE_BOUND('',#1455,.T.);
#1457=ADVANCED_FACE('F549',(#1456),#1445,.T.);
#1458=CARTESIAN_POINT('',(0.,121.3,0.));
#1459=DIRECTION('',(0.,0.,-1.));
#1460=DIRECTION('',(-1.,0.,0.));
#1461=AXIS2_PLACEMENT_3D('',#1458,#1459,#1460);
#1462=CYLINDRICAL_SURFACE('',#1461,9.);
#1463=CARTESIAN_POINT('',(0.,121.3,-30.25));
#1464=DIRECTION('',(0.,0.,-1.));
#1465=DIRECTION('',(-1.,0.,0.));
#1466=AXIS2_PLACEMENT_3D('',#1463,#1464,#1465);
#1467=CIRCLE('',#1466,9.);
#1468=CARTESIAN_POINT('',(-8.99999999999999,121.3,-30.25));
#1469=VERTEX_POINT('',#1468);
#1470=EDGE_CURVE('E379',#1469,#1469,#1467,.T.);
#1471=ORIENTED_EDGE('',*,*,#1470,.T.);
#1472=EDGE_LOOP('',(#1471));
#1473=FACE_BOUND('',#1472,.T.);
#1474=ORIENTED_EDGE('',*,*,#1120,.F.);
#1475=EDGE_LOOP('',(#1474));
#1476=FACE_BOUND('',#1475,.T.);
#1477=ADVANCED_FACE('F545',(#1473,#1476),#1462,.F.);
#1478=CARTESIAN_POINT('',(50.,42.5,-30.25));
#1479=DIRECTION('',(0.,0.,1.));
#1480=DIRECTION('',(1.,0.,0.));
#1481=AXIS2_PLACEMENT_3D('',#1478,#1479,#1480);
#1482=CYLINDRICAL_SURFACE('',#1481,7.5);
#1483=ORIENTED_EDGE('',*,*,#1143,.F.);
#1484=EDGE_LOOP('',(#1483));
#1485=FACE_BOUND('',#1484,.T.);
#1486=CARTESIAN_POINT('',(50.,42.5,-30.25));
#1487=DIRECTION('',(0.,0.,1.));
#1488=DIRECTION('',(1.,0.,0.));
#1489=AXIS2_PLACEMENT_3D('',#1486,#1487,#1488);
#1490=CIRCLE('',#1489,7.5);
#1491=CARTESIAN_POINT('',(57.5,42.5,-30.25));
#1492=VERTEX_POINT('',#1491);
#1493=EDGE_CURVE('E376',#1492,#1492,#1490,.F.);
#1494=ORIENTED_EDGE('',*,*,#1493,.T.);
#1495=EDGE_LOOP('',(#1494));
#1496=FACE_BOUND('',#1495,.T.);
#1497=ADVANCED_FACE('F548',(#1485,#1496),#1482,.F.);
#1498=CARTESIAN_POINT('',(79.9999999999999,146.5,-30.25));
#1499=DIRECTION('',(0.,0.,1.));
#1500=DIRECTION('',(1.,0.,0.));
#1501=AXIS2_PLACEMENT_3D('',#1498,#1499,#1500);
#1502=CYLINDRICAL_SURFACE('',#1501,7.49999999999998);
#1503=ORIENTED_EDGE('',*,*,#1163,.F.);
#1504=EDGE_LOOP('',(#1503));
#1505=FACE_BOUND('',#1504,.T.);
#1506=CARTESIAN_POINT('',(79.9999999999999,146.5,-30.25));
#1507=DIRECTION('',(0.,0.,1.));
#1508=DIRECTION('',(1.,0.,0.));
#1509=AXIS2_PLACEMENT_3D('',#1506,#1507,#1508);
#1510=CIRCLE('',#1509,7.49999999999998);
#1511=CARTESIAN_POINT('',(87.4999999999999,146.5,-30.25));
#1512=VERTEX_POINT('',#1511);
#1513=EDGE_CURVE('E373',#1512,#1512,#1510,.F.);
#1514=ORIENTED_EDGE('',*,*,#1513,.T.);
#1515=EDGE_LOOP('',(#1514));
#1516=FACE_BOUND('',#1515,.T.);
#1517=ADVANCED_FACE('F18',(#1505,#1516),#1502,.F.);
#1518=CARTESIAN_POINT('',(67.5000000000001,11.,0.));
#1519=DIRECTION('',(0.,0.,-1.));
#1520=DIRECTION('',(-1.,0.,0.));
#1521=AXIS2_PLACEMENT_3D('',#1518,#1519,#1520);
#1522=CYLINDRICAL_SURFACE('',#1521,4.);
#1523=CARTESIAN_POINT('',(67.5000000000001,11.,-30.25));
#1524=DIRECTION('',(0.,0.,-1.));
#1525=DIRECTION('',(-1.,0.,0.));
#1526=AXIS2_PLACEMENT_3D('',#1523,#1524,#1525);
#1527=CIRCLE('',#1526,4.);
#1528=CARTESIAN_POINT('',(63.5000000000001,11.,-30.25));
#1529=VERTEX_POINT('',#1528);
#1530=EDGE_CURVE('E370',#1529,#1529,#1527,.T.);
#1531=ORIENTED_EDGE('',*,*,#1530,.T.);
#1532=EDGE_LOOP('',(#1531));
#1533=FACE_BOUND('',#1532,.T.);
#1534=ORIENTED_EDGE('',*,*,#1227,.F.);
#1535=EDGE_LOOP('',(#1534));
#1536=FACE_BOUND('',#1535,.T.);
#1537=ADVANCED_FACE('F540',(#1533,#1536),#1522,.F.);
#1538=CARTESIAN_POINT('',(22.5000000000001,11.,0.));
#1539=DIRECTION('',(0.,0.,-1.));
#1540=DIRECTION('',(-1.,0.,0.));
#1541=AXIS2_PLACEMENT_3D('',#1538,#1539,#1540);
#1542=CYLINDRICAL_SURFACE('',#1541,4.);
#1543=ORIENTED_EDGE('',*,*,#1191,.F.);
#1544=EDGE_LOOP('',(#1543));
#1545=FACE_BOUND('',#1544,.T.);
#1546=CARTESIAN_POINT('',(22.5000000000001,11.,-30.25));
#1547=DIRECTION('',(0.,0.,-1.));
#1548=DIRECTION('',(-1.,0.,0.));
#1549=AXIS2_PLACEMENT_3D('',#1546,#1547,#1548);
#1550=CIRCLE('',#1549,4.);
#1551=CARTESIAN_POINT('',(18.5000000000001,11.,-30.25));
#1552=VERTEX_POINT('',#1551);
#1553=EDGE_CURVE('E367',#1552,#1552,#1550,.T.);
#1554=ORIENTED_EDGE('',*,*,#1553,.T.);
#1555=EDGE_LOOP('',(#1554));
#1556=FACE_BOUND('',#1555,.T.);
#1557=ADVANCED_FACE('F536',(#1545,#1556),#1542,.F.);
#1558=CARTESIAN_POINT('',(-22.4999999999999,11.,0.));
#1559=DIRECTION('',(0.,0.,-1.));
#1560=DIRECTION('',(-1.,0.,0.));
#1561=AXIS2_PLACEMENT_3D('',#1558,#1559,#1560);
#1562=CYLINDRICAL_SURFACE('',#1561,4.);
#1563=ORIENTED_EDGE('',*,*,#1180,.F.);
#1564=EDGE_LOOP('',(#1563));
#1565=FACE_BOUND('',#1564,.T.);
#1566=CARTESIAN_POINT('',(-22.4999999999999,11.,-30.25));
#1567=DIRECTION('',(0.,0.,-1.));
#1568=DIRECTION('',(-1.,0.,0.));
#1569=AXIS2_PLACEMENT_3D('',#1566,#1567,#1568);
#1570=CIRCLE('',#1569,4.);
#1571=CARTESIAN_POINT('',(-26.4999999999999,11.,-30.25));
#1572=VERTEX_POINT('',#1571);
#1573=EDGE_CURVE('E26',#1572,#1572,#1570,.T.);
#1574=ORIENTED_EDGE('',*,*,#1573,.T.);
#1575=EDGE_LOOP('',(#1574));
#1576=FACE_BOUND('',#1575,.T.);
#1577=ADVANCED_FACE('F528',(#1565,#1576),#1562,.F.);
#1578=CARTESIAN_POINT('',(-67.4999999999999,11.,0.));
#1579=DIRECTION('',(0.,0.,-1.));
#1580=DIRECTION('',(-1.,0.,0.));
#1581=AXIS2_PLACEMENT_3D('',#1578,#1579,#1580);
#1582=CYLINDRICAL_SURFACE('',#1581,4.);
#1583=CARTESIAN_POINT('',(-67.4999999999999,11.,-30.25));
#1584=DIRECTION('',(0.,0.,-1.));
#1585=DIRECTION('',(-1.,0.,0.));
#1586=AXIS2_PLACEMENT_3D('',#1583,#1584,#1585);
#1587=CIRCLE('',#1586,4.);
#1588=CARTESIAN_POINT('',(-71.5,11.,-30.25));
#1589=VERTEX_POINT('',#1588);
#1590=EDGE_CURVE('E11',#1589,#1589,#1587,.T.);
#1591=ORIENTED_EDGE('',*,*,#1590,.T.);
#1592=EDGE_LOOP('',(#1591));
#1593=FACE_BOUND('',#1592,.T.);
#1594=ORIENTED_EDGE('',*,*,#1238,.F.);
#1595=EDGE_LOOP('',(#1594));
#1596=FACE_BOUND('',#1595,.T.);
#1597=ADVANCED_FACE('F522',(#1593,#1596),#1582,.F.);
#1598=CARTESIAN_POINT('',(0.,84.,-30.25));
#1599=DIRECTION('',(0.,0.,1.));
#1600=DIRECTION('',(1.,0.,0.));
#1601=AXIS2_PLACEMENT_3D('',#1598,#1599,#1600);
#1602=PLANE('',#1601);
#1603=ORIENTED_EDGE('',*,*,#1590,.F.);
#1604=EDGE_LOOP('',(#1603));
#1605=FACE_BOUND('',#1604,.T.);
#1606=ORIENTED_EDGE('',*,*,#1573,.F.);
#1607=EDGE_LOOP('',(#1606));
#1608=FACE_BOUND('',#1607,.T.);
#1609=ORIENTED_EDGE('',*,*,#1553,.F.);
#1610=EDGE_LOOP('',(#1609));
#1611=FACE_BOUND('',#1610,.T.);
#1612=ORIENTED_EDGE('',*,*,#1530,.F.);
#1613=EDGE_LOOP('',(#1612));
#1614=FACE_BOUND('',#1613,.T.);
#1615=ORIENTED_EDGE('',*,*,#1513,.F.);
#1616=EDGE_LOOP('',(#1615));
#1617=FACE_BOUND('',#1616,.T.);
#1618=ORIENTED_EDGE('',*,*,#1493,.F.);
#1619=EDGE_LOOP('',(#1618));
#1620=FACE_BOUND('',#1619,.T.);
#1621=ORIENTED_EDGE('',*,*,#1470,.F.);
#1622=EDGE_LOOP('',(#1621));
#1623=FACE_BOUND('',#1622,.T.);
#1624=ORIENTED_EDGE('',*,*,#1429,.F.);
#1625=ORIENTED_EDGE('',*,*,#1406,.F.);
#1626=ORIENTED_EDGE('',*,*,#1388,.F.);
#1627=ORIENTED_EDGE('',*,*,#1350,.F.);
#1628=ORIENTED_EDGE('',*,*,#1319,.F.);
#1629=ORIENTED_EDGE('',*,*,#1452,.F.);
#1630=EDGE_LOOP('',(#1624,#1625,#1626,#1627,#1628,#1629));
#1631=FACE_BOUND('',#1630,.T.);
#1632=ADVANCED_FACE('F520',(#1605,#1608,#1611,#1614,#1617,#1620,#1623,#1631),#1602,.F.);
#1633=CLOSED_SHELL('',(#35,#55,#72,#100,#120,#140,#160,#188,#228,#261,#292,#325,#358,#391,#422,
#455,#486,#528,#559,#592,#625,#656,#689,#720,#753,#786,#817,#850,#870,#890,#918,#949,#980,#1011,
#1042,#1107,#1127,#1147,#1167,#1214,#1305,#1338,#1366,#1392,#1416,#1440,#1457,#1477,#1497,#1517,
#1537,#1557,#1577,#1597,#1632));
#1634=MANIFOLD_SOLID_BREP('B1',#1633);
#1635=ADVANCED_BREP_SHAPE_REPRESENTATION('',(#18,#1634),#14);
#1636=SHAPE_DEFINITION_REPRESENTATION(#9,#1635);
ENDSEC;
END-ISO-10303-21;
